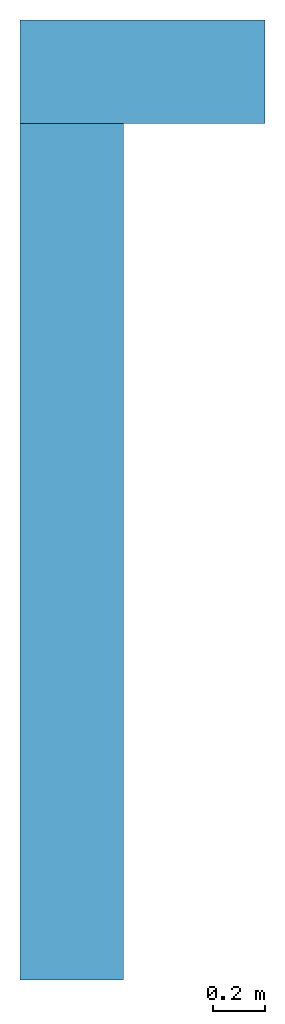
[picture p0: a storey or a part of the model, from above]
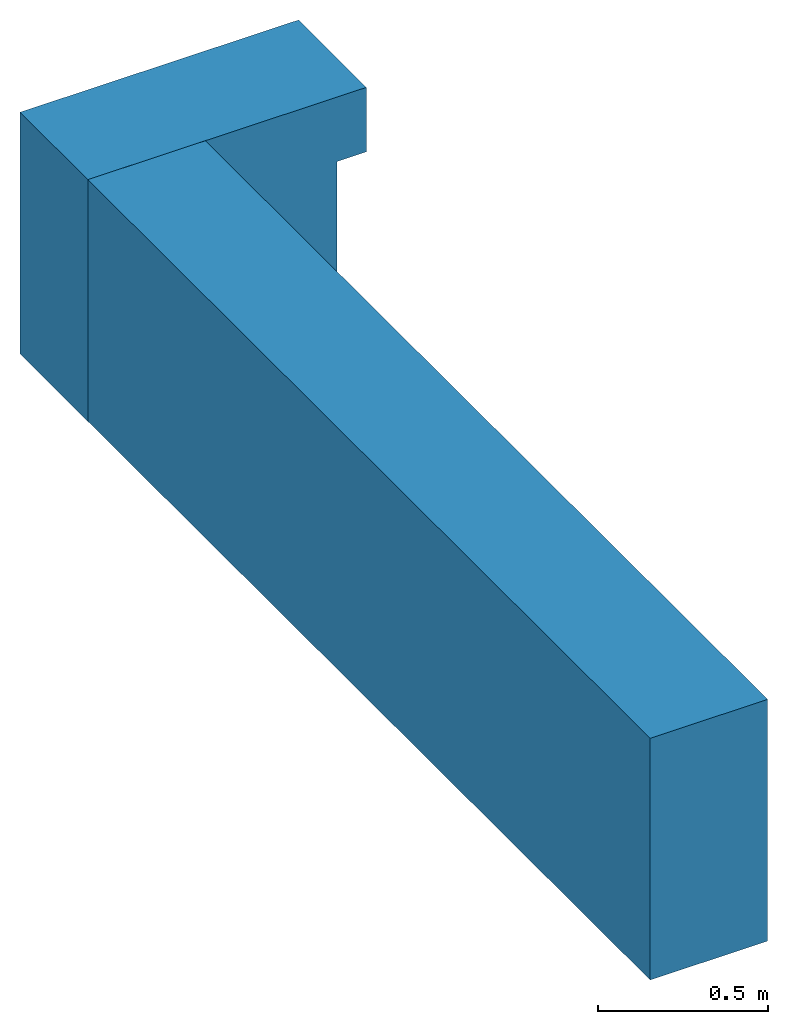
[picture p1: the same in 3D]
Properties of the parts of a building model (IFC2X3), part 1 of 3

# File
Description: ViewDefinition [CoordinationView]
File name: VA006-350-101.1 (EDITED).ifc (Edited by Naviate Simple BIM 2022 version 6)
Time: 2026-03-20T14:23:12+01:00
Written by: ODA SDAI 22.12
Made in: Autodesk Revit 23.1.90.15 (ENU) - IFC 23.3.1.0

# IfcProject
LongName: Trondheim Lufthavn Værnes; Phase: TU 2013

# IfcSite, Default
RefLatitude: 59, 54, 57, 601318; RefLongitude: 10, 44, 59, 999999; RefElevation: 0 mm
Data - Ideate BIMLink: <?xml version="1.0" encoding="utf-8"?><application version="3"> <links> <link> <name>Casework Types</name> <description></description> <elements>CaseworkTypes</elements> <phase>Fase 2</phase> <phase_filter>None</phase_filter> <properties> <property> <name>Id</name> <lookup_1_type></lookup_1_type> <lookup_1_id></lookup_1_id> <type>BUILT_IN_PARAMETER</type> <id>ID_PARAM</id> </property> <property> <name>Family Name</name> <lookup_1_type></lookup_1_type> <lookup_1_id></lookup_1_id> <type>CALCULATED_PROPERTY</type> <id>FamilyName</id> </property> <property> <name>Type Name</name> <lookup_1_type></lookup_1_type> <lookup_1_id></lookup_1_id> <type>CALCULATED_PROPERTY</type> <id>TypeName</id> </property> </properties> </link> <link> <name>Window Types</name> <description></description> <elements>WindowTypes</elements> <phase>Fase 2</phase> <phase_filter>None</phase_filter> <properties> <property> <name>Id</name> <lookup_1_type></lookup_1_type> <lookup_1_id></lookup_1_id> <type>BUILT_IN_PARAMETER</type> <id>ID_PARAM</id> </property> <property> <name>Family Name</name> <lookup_1_type></lookup_1_type> <lookup_1_id></lookup_1_id> <type>CALCULATED_PROPERTY</type> <id>FamilyName</id> </property> <property> <name>Type Name</name> <lookup_1_type></lookup_1_type> <lookup_1_id></lookup_1_id> <type>CALCULATED_PROPERTY</type> <id>TypeName</id> </property> </properties> </link> <link> <name>Wall Types</name> <description></description> <elements>WallTypes</elements> <phase>Fase 1</phase> <phase_filter>Show Complete</phase_filter> <properties> <property> <name>Id</name> <lookup_1_type></lookup_1_type> <lookup_1_id></lookup_1_id> <type>BUILT_IN_PARAMETER</type> <id>ID_PARAM</id> </property> <property> <name>Family Name</name> <lookup_1_type></lookup_1_type> <lookup_1_id></lookup_1_id> <type>BUILT_IN_PARAMETER</type> <id>SYMBOL_FAMILY_NAME_PARAM</id> </property> <property> <name>Type Name</name> <lookup_1_type></lookup_1_type> <lookup_1_id></lookup_1_id> <type>CALCULATED_PROPERTY</type> <id>TypeName</id> </property> </properties> </link> <link> <name>Structural Framing Types</name> <description></description> <elements>StructuralFramingTypes</elements> <phase>Fase 2</phase> <phase_filter>None</phase_filter> <properties> <property> <name>Id</name> <lookup_1_type></lookup_1_type> <lookup_1_id></lookup_1_id> <type>BUILT_IN_PARAMETER</type> <id>ID_PARAM</id> </property> <property> <name>Family Name</name> <lookup_1_type></lookup_1_type> <lookup_1_id></lookup_1_id> <type>CALCULATED_PROPERTY</type> <id>FamilyName</id> </property> <property> <name>Type Name</name> <lookup_1_type></lookup_1_type> <lookup_1_id></lookup_1_id> <type>CALCULATED_PROPERTY</type> <id>TypeName</id> </property> </properties> </link> <link> <name>Structural Foundation Types</name> <description></description> <elements>StructuralFoundationTypes</elements> <phase>Fase 2</phase> <phase_filter>None</phase_filter> <properties> <property> <name>Id</name> <lookup_1_type></lookup_1_type> <lookup_1_id></lookup_1_id> <type>BUILT_IN_PARAMETER</type> <id>ID_PARAM</id> </property> <property> <name>Family Name</name> <lookup_1_type></lookup_1_type> <lookup_1_id></lookup_1_id> <type>CALCULATED_PROPERTY</type> <id>FamilyName</id> </property> <property> <name>Type Name</name> <lookup_1_type></lookup_1_type> <lookup_1_id></lookup_1_id> <type>CALCULATED_PROPERTY</type> <id>TypeName</id> </property> </properties> </link> <link> <name>Structural Column Types</name> <description></description> <elements>StructuralColumnTypes</elements> <phase>Fase 2</phase> <phase_filter>None</phase_filter> <properties> <property> <name>Id</name> <lookup_1_type></lookup_1_type> <lookup_1_id></lookup_1_id> <type>BUILT_IN_PARAMETER</type> <id>ID_PARAM</id> </property> <property> <name>Family Name</name> <lookup_1_type></lookup_1_type> <lookup_1_id></lookup_1_id> <type>CALCULATED_PROPERTY</type> <id>FamilyName</id> </property> <property> <name>Type Name</name> <lookup_1_type></lookup_1_type> <lookup_1_id></lookup_1_id> <type>CALCULATED_PROPERTY</type> <id>TypeName</id> </property> </properties> </link> <link> <name>Stair Types</name> <description></description> <elements>StairTypes</elements> <phase>Fase 2</phase> <phase_filter>None</phase_filter> <properties> <property> <name>Id</name> <lookup_1_type></lookup_1_type> <lookup_1_id></lookup_1_id> <type>BUILT_IN_PARAMETER</type> <id>ID_PARAM</id> </property> <property> <name>Family Name</name> <lookup_1_type></lookup_1_type> <lookup_1_id></lookup_1_id> <type>BUILT_IN_PARAMETER</type> <id>ALL_MODEL_FAMILY_NAME</id> </property> <property> <name>Type Name</name> <lookup_1_type></lookup_1_type> <lookup_1_id></lookup_1_id> <type>CALCULATED_PROPERTY</type> <id>TypeName</id> </property> </properties> </link> <link> <name>Specialty Equipment Types</name> <description></description> <elements>SpecialtyEquipmentTypes</elements> <phase>Fase 2</phase> <phase_filter>None</phase_filter> <properties> <property> <name>Id</name> <lookup_1_type></lookup_1_type> <lookup_1_id></lookup_1_id> <type>BUILT_IN_PARAMETER</type> <id>ID_PARAM</id> </property> <property> <name>Family Name</name> <lookup_1_type></lookup_1_type> <lookup_1_id></lookup_1_id> <type>CALCULATED_PROPERTY</type> <id>FamilyName</id> </property> <property> <name>Type Name</name> <lookup_1_type></lookup_1_type> <lookup_1_id></lookup_1_id> <type>CALCULATED_PROPERTY</type> <id>TypeName</id> </property> </properties> </link> <link> <name>Roof Types</name> <description></description> <elements>RoofTypes</elements> <phase>Fase 2</phase> <phase_filter>None</phase_filter> <properties> <property> <name>Id</name> <lookup_1_type></lookup_1_type> <lookup_1_id></lookup_1_id> <type>BUILT_IN_PARAMETER</type> <id>ID_PARAM</id> </property> <property> <name>Family Name</name> <lookup_1_type></lookup_1_type> <lookup_1_id></lookup_1_id> <type>BUILT_IN_PARAMETER</type> <id>ALL_MODEL_FAMILY_NAME</id> </property> <property> <name>Type Name</name> <lookup_1_type></lookup_1_type> <lookup_1_id></lookup_1_id> <type>CALCULATED_PROPERTY</type> <id>TypeName</id> </property> </properties> </link> <link> <name>Ramp Types</name> <description></description> <elements>RampTypes</elements> <phase>Fase 2</phase> <phase_filter>None</phase_filter> <properties> <property> <name>Id</name> <lookup_1_type></lookup_1_type> <lookup_1_id></lookup_1_id> <type>BUILT_IN_PARAMETER</type> <id>ID_PARAM</id> </property> <property> <name>Family Name</name> <lookup_1_type></lookup_1_type> <lookup_1_id></lookup_1_id> <type>BUILT_IN_PARAMETER</type> <id>ALL_MODEL_FAMILY_NAME</id> </property> <property> <name>Type Name</name> <lookup_1_type></lookup_1_type> <lookup_1_id></lookup_1_id> <type>CALCULATED_PROPERTY</type> <id>TypeName</id> </property> </properties> </link> <link> <name>Railing Types</name> <description></description> <elements>RailingTypes</elements> <phase>Fase 2</phase> <phase_filter>None</phase_filter> <properties> <property> <name>Id</name> <lookup_1_type></lookup_1_type> <lookup_1_id></lookup_1_id> <type>BUILT_IN_PARAMETER</type> <id>ID_PARAM</id> </property> <property> <name>Family Name</name> <lookup_1_type></lookup_1_type> <lookup_1_id></lookup_1_id> <type>BUILT_IN_PARAMETER</type> <id>ALL_MODEL_FAMILY_NAME</id> </property> <property> <name>Type Name</name> <lookup_1_type></lookup_1_type> <lookup_1_id></lookup_1_id> <type>CALCULATED_PROPERTY</type> <id>TypeName</id> </property> </properties> </link> <link> <name>Profile Types</name> <description></description> <elements>ProfileTypes</elements> <phase>Fase 2</phase> <phase_filter>None</phase_filter> <properties> <property> <name>Id</name> <lookup_1_type></lookup_1_type> <lookup_1_id></lookup_1_id> <type>BUILT_IN_PARAMETER</type> <id>ID_PARAM</id> </property> <property> <name>Family Name</name> <lookup_1_type></lookup_1_type> <lookup_1_id></lookup_1_id> <type>BUILT_IN_PARAMETER</type> <id>ALL_MODEL_FAMILY_NAME</id> </property> <property> <name>Type Name</name> <lookup_1_type></lookup_1_type> <lookup_1_id></lookup_1_id> <type>CALCULATED_PROPERTY</type> <id>TypeName</id> </property> </properties> </link> <link> <name>Plumbing Fixture Types</name> <description></description> <elements>PlumbingFixtureTypes</elements> <phase>Fase 2</phase> <phase_filter>None</phase_filter> <properties> <property> <name>Id</name> <lookup_1_type></lookup_1_type> <lookup_1_id></lookup_1_id> <type>BUILT_IN_PARAMETER</type> <id>ID_PARAM</id> </property> <property> <name>Family Name</name> <lookup_1_type></lookup_1_type> <lookup_1_id></lookup_1_id> <type>CALCULATED_PROPERTY</type> <id>FamilyName</id> </property> <property> <name>Type Name</name> <lookup_1_type></lookup_1_type> <lookup_1_id></lookup_1_id> <type>CALCULATED_PROPERTY</type> <id>TypeName</id> </property> </properties> </link> <link> <name>Mechanical Equipment Types</name> <description></description> <elements>MechanicalEquipmentTypes</elements> <phase>Fase 2</phase> <phase_filter>None</phase_filter> <properties> <property> <name>Id</name> <lookup_1_type></lookup_1_type> <lookup_1_id></lookup_1_id> <type>BUILT_IN_PARAMETER</type> <id>ID_PARAM</id> </property> <property> <name>Family Name</name> <lookup_1_type></lookup_1_type> <lookup_1_id></lookup_1_id> <type>CALCULATED_PROPERTY</type> <id>FamilyName</id> </property> <property> <name>Type Name</name> <lookup_1_type></lookup_1_type> <lookup_1_id></lookup_1_id> <type>CALCULATED_PROPERTY</type> <id>TypeName</id> </property> </properties> </link> <link> <name>Mass Types</name> <description></description> <elements>MassTypes</elements> <phase>Fase 2</phase> <phase_filter>None</phase_filter> <properties> <property> <name>Id</name> <lookup_1_type></lookup_1_type> <lookup_1_id></lookup_1_id> <type>BUILT_IN_PARAMETER</type> <id>ID_PARAM</id> </property> <property> <name>Family Name</name> <lookup_1_type></lookup_1_type> <lookup_1_id></lookup_1_id> <type>CALCULATED_PROPERTY</type> <id>FamilyName</id> </property> <property> <name>Type Name</name> <lookup_1_type></lookup_1_type> <lookup_1_id></lookup_1_id> <type>CALCULATED_PROPERTY</type> <id>TypeName</id> </property> </properties> </link> <link> <name>Generic Model Types</name> <description></description> <elements>GenericModelTypes</elements> <phase>Fase 2</phase> <phase_filter>None</phase_filter> <properties> <property> <name>Id</name> <lookup_1_type></lookup_1_type> <lookup_1_id></lookup_1_id> <type>BUILT_IN_PARAMETER</type> <id>ID_PARAM</id> </property> <property> <name>Family Name</name> <lookup_1_type></lookup_1_type> <lookup_1_id></lookup_1_id> <type>CALCULATED_PROPERTY</type> <id>FamilyName</id> </property> <property> <name>Type Name</name> <lookup_1_type></lookup_1_type> <lookup_1_id></lookup_1_id> <type>CALCULATED_PROPERTY</type> <id>TypeName</id> </property> </properties> </link> <link> <name>Column Types</name> <description></description> <elements>ColumnTypes</elements> <phase>Fase 2</phase> <phase_filter>None</phase_filter> <properties> <property> <name>Id</name> <lookup_1_type></lookup_1_type> <lookup_1_id></lookup_1_id> <type>BUILT_IN_PARAMETER</type> <id>ID_PARAM</id> </property> <property> <name>Family Name</name> <lookup_1_type></lookup_1_type> <lookup_1_id></lookup_1_id> <type>CALCULATED_PROPERTY</type> <id>FamilyName</id> </property> <property> <name>Type Name</name> <lookup_1_type></lookup_1_type> <lookup_1_id></lookup_1_id> <type>CALCULATED_PROPERTY</type> <id>TypeName</id> </property> </properties> </link> <link> <name>Columns</name> <description></description> <elements>ColumnInstances</elements> <phase>Fase 2</phase> <phase_filter>None</phase_filter> <properties> <property> <name>Id</name> <lookup_1_type></lookup_1_type> <lookup_1_id></lookup_1_id> <type>BUILT_IN_PARAMETER</type> <id>ID_PARAM</id> </property> </properties> </link> <link> <name>Door Types</name> <description></description> <elements>DoorTypes</elements> <phase>Fase 2</phase> <phase_filter>None</phase_filter> <properties> <property> <name>Id</name> <lookup_1_type></lookup_1_type> <lookup_1_id></lookup_1_id> <type>BUILT_IN_PARAMETER</type> <id>ID_PARAM</id> </property> <property> <name>Family Name</name> <lookup_1_type></lookup_1_type> <lookup_1_id></lookup_1_id> <type>CALCULATED_PROPERTY</type> <id>FamilyName</id> </property> <property> <name>Type Name</name> <lookup_1_type></lookup_1_type> <lookup_1_id></lookup_1_id> <type>CALCULATED_PROPERTY</type> <id>TypeName</id> </property> </properties> </link> <link> <name>Door Types 2</name> <description></description> <elements>DoorTypes</elements> <phase>Fase 1</phase> <phase_filter>Show Complete</phase_filter> <properties> <property> <name>Id</name> <lookup_1_type></lookup_1_type> <lookup_1_id></lookup_1_id> <type>BUILT_IN_PARAMETER</type> <id>ID_PARAM</id> </property> <property> <name>Family Name</name> <lookup_1_type></lookup_1_type> <lookup_1_id></lookup_1_id> <type>CALCULATED_PROPERTY</type> <id>FamilyName</id> </property> <property> <name>Type Name</name> <lookup_1_type></lookup_1_type> <lookup_1_id></lookup_1_id> <type>CALCULATED_PROPERTY</type> <id>TypeName</id> </property> </properties> </link> <link> <name>Ceiling Types</name> <description></description> <elements>CeilingTypes</elements> <phase>Fase 2</phase> <phase_filter>None</phase_filter> <properties> <property> <name>Id</name> <lookup_1_type></lookup_1_type> <lookup_1_id></lookup_1_id> <type>BUILT_IN_PARAMETER</type> <id>ID_PARAM</id> </property> <property> <name>Family Name</name> <lookup_1_type></lookup_1_type> <lookup_1_id></lookup_1_id> <type>BUILT_IN_PARAMETER</type> <id>ALL_MODEL_FAMILY_NAME</id> </property> <property> <name>Type Name</name> <lookup_1_type></lookup_1_type> <lookup_1_id></lookup_1_id> <type>CALCULATED_PROPERTY</type> <id>TypeName</id> </property> </properties> </link> <link> <name>Ceilings</name> <description></description> <elements>CeilingInstances</elements> <phase>Fase 2</phase> <phase_filter>None</phase_filter> <properties> <property> <name>Id</name> <lookup_1_type></lookup_1_type> <lookup_1_id></lookup_1_id> <type>BUILT_IN_PARAMETER</type> <id>ID_PARAM</id> </property> <property> <name>Family Name</name> <lookup_1_type>BUILT_IN_PARAMETER</lookup_1_type> <lookup_1_id>SYMBOL_ID_PARAM</lookup_1_id> <type>BUILT_IN_PARAMETER</type> <id>ALL_MODEL_FAMILY_NAME</id> </property> <property> <name>Type Name</name> <lookup_1_type>BUILT_IN_PARAMETER</lookup_1_type> <lookup_1_id>SYMBOL_ID_PARAM</lookup_1_id> <type>CALCULATED_PROPERTY</type> <id>TypeName</id> </property> </properties> </link> <link> <name>Furniture Types</name> <description></description> <elements>FurnitureTypes</elements> <phase>Fase 2</phase> <phase_filter>None</phase_filter> <properties> <property> <name>Id</name> <lookup_1_type></lookup_1_type> <lookup_1_id></lookup_1_id> <type>BUILT_IN_PARAMETER</type> <id>ID_PARAM</id> </property> <property> <name>Family Name</name> <lookup_1_type></lookup_1_type> <lookup_1_id></lookup_1_id> <type>CALCULATED_PROPERTY</type> <id>FamilyName</id> </property> <property> <name>Type Name</name> <lookup_1_type></lookup_1_type> <lookup_1_id></lookup_1_id> <type>CALCULATED_PROPERTY</type> <id>TypeName</id> </property> </properties> </link> <link> <name>Furniture System Types</name> <description></description> <elements>FurnitureSystemTypes</elements> <phase>Fase 2</phase> <phase_filter>None</phase_filter> <properties> <property> <name>Id</name> <lookup_1_type></lookup_1_type> <lookup_1_id></lookup_1_id> <type>BUILT_IN_PARAMETER</type> <id>ID_PARAM</id> </property> <property> <name>Family Name</name> <lookup_1_type></lookup_1_type> <lookup_1_id></lookup_1_id> <type>CALCULATED_PROPERTY</type> <id>FamilyName</id> </property> <property> <name>Type Name</name> <lookup_1_type></lookup_1_type> <lookup_1_id></lookup_1_id> <type>CALCULATED_PROPERTY</type> <id>TypeName</id> </property> </properties> </link> <link> <name>Sheets</name> <description></description> <elements>Sheets</elements> <phase>Fase 1</phase> <phase_filter>None</phase_filter> <properties> <property> <name>Id</name> <lookup_1_type></lookup_1_type> <lookup_1_id></lookup_1_id> <type>BUILT_IN_PARAMETER</type> <id>ID_PARAM</id> </property> </properties> </link> <link> <name>Walls</name> <description></description> <elements>WallInstances</elements> <phase>Fase 2</phase> <phase_filter>None</phase_filter> <properties> <property> <name>Id</name> <lookup_1_type></lookup_1_type> <lookup_1_id></lookup_1_id> <type>BUILT_IN_PARAMETER</type> <id>ID_PARAM</id> </property> </properties> </link> <link> <name>Wall types all official names</name> <description></description> <elements>WallTypes</elements> <phase>Fase 1</phase> <phase_filter>None</phase_filter> <properties> <property> <name>Id</name> <lookup_1_type></lookup_1_type> <lookup_1_id></lookup_1_id> <type>BUILT_IN_PARAMETER</type> <id>ID_PARAM</id> </property> <property> <name>Family Name</name> <lookup_1_type></lookup_1_type> <lookup_1_id></lookup_1_id> <type>BUILT_IN_PARAMETER</type> <id>ALL_MODEL_FAMILY_NAME</id> </property> <property> <name>Type Name</name> <lookup_1_type></lookup_1_type> <lookup_1_id></lookup_1_id> <type>CALCULATED_PROPERTY</type> <id>TypeName</id> </property> </properties> </link> <link> <name>test</name> <description></description> <elements>WallTypes</elements> <phase>Fase 1</phase> <phase_filter>None</phase_filter> <properties> <property> <name>Id</name> <lookup_1_type></lookup_1_type> <lookup_1_id></lookup_1_id> <type>BUILT_IN_PARAMETER</type> <id>ID_PARAM</id> </property> <property> <name>Family Name</name> <lookup_1_type></lookup_1_type> <lookup_1_id></lookup_1_id> <type>BUILT_IN_PARAMETER</type> <id>ALL_MODEL_FAMILY_NAME</id> </property> <property> <name>Type Name</name> <lookup_1_type></lookup_1_type> <lookup_1_id></lookup_1_id> <type>CALCULATED_PROPERTY</type> <id>TypeName</id> </property> </properties> </link> </links></application>
Text - 01_Modellfil: va006-a-220-1-0001.rvt
Identity Data - Workset: Project Info
Other - RIE, firma: RAMBØLL AS; Project Status: TU 2013; Saksbehandler: MR; Project Address: Skriv adresse her; Category: Project Information; Prosjektansvarlig: TILBUD E203 TETT BYGG; RIV, telefon: +47 7310 6200; RIB, telefon: +47 7289 3750; Project Name: Trondheim Lufthavn Værnes; RIV, firma: MULTICONSULT AS; RIB, firma: NORCONSULT; RIE, telefon: +47 7389 1000

# IfcBuilding
Pset_BuildingCommon - NumberOfStoreys: 9
Text - 01_Modellfil: va006-a-220-1-0001.rvt
Identity Data - Workset: Project Info
Data - Ideate BIMLink: <?xml version="1.0" encoding="utf-8"?><application version="3"> <links> <link> <name>Casework Types</name> <description></description> <elements>CaseworkTypes</elements> <phase>Fase 2</phase> <phase_filter>None</phase_filter> <properties> <property> <name>Id</name> <lookup_1_type></lookup_1_type> <lookup_1_id></lookup_1_id> <type>BUILT_IN_PARAMETER</type> <id>ID_PARAM</id> </property> <property> <name>Family Name</name> <lookup_1_type></lookup_1_type> <lookup_1_id></lookup_1_id> <type>CALCULATED_PROPERTY</type> <id>FamilyName</id> </property> <property> <name>Type Name</name> <lookup_1_type></lookup_1_type> <lookup_1_id></lookup_1_id> <type>CALCULATED_PROPERTY</type> <id>TypeName</id> </property> </properties> </link> <link> <name>Window Types</name> <description></description> <elements>WindowTypes</elements> <phase>Fase 2</phase> <phase_filter>None</phase_filter> <properties> <property> <name>Id</name> <lookup_1_type></lookup_1_type> <lookup_1_id></lookup_1_id> <type>BUILT_IN_PARAMETER</type> <id>ID_PARAM</id> </property> <property> <name>Family Name</name> <lookup_1_type></lookup_1_type> <lookup_1_id></lookup_1_id> <type>CALCULATED_PROPERTY</type> <id>FamilyName</id> </property> <property> <name>Type Name</name> <lookup_1_type></lookup_1_type> <lookup_1_id></lookup_1_id> <type>CALCULATED_PROPERTY</type> <id>TypeName</id> </property> </properties> </link> <link> <name>Wall Types</name> <description></description> <elements>WallTypes</elements> <phase>Fase 1</phase> <phase_filter>Show Complete</phase_filter> <properties> <property> <name>Id</name> <lookup_1_type></lookup_1_type> <lookup_1_id></lookup_1_id> <type>BUILT_IN_PARAMETER</type> <id>ID_PARAM</id> </property> <property> <name>Family Name</name> <lookup_1_type></lookup_1_type> <lookup_1_id></lookup_1_id> <type>BUILT_IN_PARAMETER</type> <id>SYMBOL_FAMILY_NAME_PARAM</id> </property> <property> <name>Type Name</name> <lookup_1_type></lookup_1_type> <lookup_1_id></lookup_1_id> <type>CALCULATED_PROPERTY</type> <id>TypeName</id> </property> </properties> </link> <link> <name>Structural Framing Types</name> <description></description> <elements>StructuralFramingTypes</elements> <phase>Fase 2</phase> <phase_filter>None</phase_filter> <properties> <property> <name>Id</name> <lookup_1_type></lookup_1_type> <lookup_1_id></lookup_1_id> <type>BUILT_IN_PARAMETER</type> <id>ID_PARAM</id> </property> <property> <name>Family Name</name> <lookup_1_type></lookup_1_type> <lookup_1_id></lookup_1_id> <type>CALCULATED_PROPERTY</type> <id>FamilyName</id> </property> <property> <name>Type Name</name> <lookup_1_type></lookup_1_type> <lookup_1_id></lookup_1_id> <type>CALCULATED_PROPERTY</type> <id>TypeName</id> </property> </properties> </link> <link> <name>Structural Foundation Types</name> <description></description> <elements>StructuralFoundationTypes</elements> <phase>Fase 2</phase> <phase_filter>None</phase_filter> <properties> <property> <name>Id</name> <lookup_1_type></lookup_1_type> <lookup_1_id></lookup_1_id> <type>BUILT_IN_PARAMETER</type> <id>ID_PARAM</id> </property> <property> <name>Family Name</name> <lookup_1_type></lookup_1_type> <lookup_1_id></lookup_1_id> <type>CALCULATED_PROPERTY</type> <id>FamilyName</id> </property> <property> <name>Type Name</name> <lookup_1_type></lookup_1_type> <lookup_1_id></lookup_1_id> <type>CALCULATED_PROPERTY</type> <id>TypeName</id> </property> </properties> </link> <link> <name>Structural Column Types</name> <description></description> <elements>StructuralColumnTypes</elements> <phase>Fase 2</phase> <phase_filter>None</phase_filter> <properties> <property> <name>Id</name> <lookup_1_type></lookup_1_type> <lookup_1_id></lookup_1_id> <type>BUILT_IN_PARAMETER</type> <id>ID_PARAM</id> </property> <property> <name>Family Name</name> <lookup_1_type></lookup_1_type> <lookup_1_id></lookup_1_id> <type>CALCULATED_PROPERTY</type> <id>FamilyName</id> </property> <property> <name>Type Name</name> <lookup_1_type></lookup_1_type> <lookup_1_id></lookup_1_id> <type>CALCULATED_PROPERTY</type> <id>TypeName</id> </property> </properties> </link> <link> <name>Stair Types</name> <description></description> <elements>StairTypes</elements> <phase>Fase 2</phase> <phase_filter>None</phase_filter> <properties> <property> <name>Id</name> <lookup_1_type></lookup_1_type> <lookup_1_id></lookup_1_id> <type>BUILT_IN_PARAMETER</type> <id>ID_PARAM</id> </property> <property> <name>Family Name</name> <lookup_1_type></lookup_1_type> <lookup_1_id></lookup_1_id> <type>BUILT_IN_PARAMETER</type> <id>ALL_MODEL_FAMILY_NAME</id> </property> <property> <name>Type Name</name> <lookup_1_type></lookup_1_type> <lookup_1_id></lookup_1_id> <type>CALCULATED_PROPERTY</type> <id>TypeName</id> </property> </properties> </link> <link> <name>Specialty Equipment Types</name> <description></description> <elements>SpecialtyEquipmentTypes</elements> <phase>Fase 2</phase> <phase_filter>None</phase_filter> <properties> <property> <name>Id</name> <lookup_1_type></lookup_1_type> <lookup_1_id></lookup_1_id> <type>BUILT_IN_PARAMETER</type> <id>ID_PARAM</id> </property> <property> <name>Family Name</name> <lookup_1_type></lookup_1_type> <lookup_1_id></lookup_1_id> <type>CALCULATED_PROPERTY</type> <id>FamilyName</id> </property> <property> <name>Type Name</name> <lookup_1_type></lookup_1_type> <lookup_1_id></lookup_1_id> <type>CALCULATED_PROPERTY</type> <id>TypeName</id> </property> </properties> </link> <link> <name>Roof Types</name> <description></description> <elements>RoofTypes</elements> <phase>Fase 2</phase> <phase_filter>None</phase_filter> <properties> <property> <name>Id</name> <lookup_1_type></lookup_1_type> <lookup_1_id></lookup_1_id> <type>BUILT_IN_PARAMETER</type> <id>ID_PARAM</id> </property> <property> <name>Family Name</name> <lookup_1_type></lookup_1_type> <lookup_1_id></lookup_1_id> <type>BUILT_IN_PARAMETER</type> <id>ALL_MODEL_FAMILY_NAME</id> </property> <property> <name>Type Name</name> <lookup_1_type></lookup_1_type> <lookup_1_id></lookup_1_id> <type>CALCULATED_PROPERTY</type> <id>TypeName</id> </property> </properties> </link> <link> <name>Ramp Types</name> <description></description> <elements>RampTypes</elements> <phase>Fase 2</phase> <phase_filter>None</phase_filter> <properties> <property> <name>Id</name> <lookup_1_type></lookup_1_type> <lookup_1_id></lookup_1_id> <type>BUILT_IN_PARAMETER</type> <id>ID_PARAM</id> </property> <property> <name>Family Name</name> <lookup_1_type></lookup_1_type> <lookup_1_id></lookup_1_id> <type>BUILT_IN_PARAMETER</type> <id>ALL_MODEL_FAMILY_NAME</id> </property> <property> <name>Type Name</name> <lookup_1_type></lookup_1_type> <lookup_1_id></lookup_1_id> <type>CALCULATED_PROPERTY</type> <id>TypeName</id> </property> </properties> </link> <link> <name>Railing Types</name> <description></description> <elements>RailingTypes</elements> <phase>Fase 2</phase> <phase_filter>None</phase_filter> <properties> <property> <name>Id</name> <lookup_1_type></lookup_1_type> <lookup_1_id></lookup_1_id> <type>BUILT_IN_PARAMETER</type> <id>ID_PARAM</id> </property> <property> <name>Family Name</name> <lookup_1_type></lookup_1_type> <lookup_1_id></lookup_1_id> <type>BUILT_IN_PARAMETER</type> <id>ALL_MODEL_FAMILY_NAME</id> </property> <property> <name>Type Name</name> <lookup_1_type></lookup_1_type> <lookup_1_id></lookup_1_id> <type>CALCULATED_PROPERTY</type> <id>TypeName</id> </property> </properties> </link> <link> <name>Profile Types</name> <description></description> <elements>ProfileTypes</elements> <phase>Fase 2</phase> <phase_filter>None</phase_filter> <properties> <property> <name>Id</name> <lookup_1_type></lookup_1_type> <lookup_1_id></lookup_1_id> <type>BUILT_IN_PARAMETER</type> <id>ID_PARAM</id> </property> <property> <name>Family Name</name> <lookup_1_type></lookup_1_type> <lookup_1_id></lookup_1_id> <type>BUILT_IN_PARAMETER</type> <id>ALL_MODEL_FAMILY_NAME</id> </property> <property> <name>Type Name</name> <lookup_1_type></lookup_1_type> <lookup_1_id></lookup_1_id> <type>CALCULATED_PROPERTY</type> <id>TypeName</id> </property> </properties> </link> <link> <name>Plumbing Fixture Types</name> <description></description> <elements>PlumbingFixtureTypes</elements> <phase>Fase 2</phase> <phase_filter>None</phase_filter> <properties> <property> <name>Id</name> <lookup_1_type></lookup_1_type> <lookup_1_id></lookup_1_id> <type>BUILT_IN_PARAMETER</type> <id>ID_PARAM</id> </property> <property> <name>Family Name</name> <lookup_1_type></lookup_1_type> <lookup_1_id></lookup_1_id> <type>CALCULATED_PROPERTY</type> <id>FamilyName</id> </property> <property> <name>Type Name</name> <lookup_1_type></lookup_1_type> <lookup_1_id></lookup_1_id> <type>CALCULATED_PROPERTY</type> <id>TypeName</id> </property> </properties> </link> <link> <name>Mechanical Equipment Types</name> <description></description> <elements>MechanicalEquipmentTypes</elements> <phase>Fase 2</phase> <phase_filter>None</phase_filter> <properties> <property> <name>Id</name> <lookup_1_type></lookup_1_type> <lookup_1_id></lookup_1_id> <type>BUILT_IN_PARAMETER</type> <id>ID_PARAM</id> </property> <property> <name>Family Name</name> <lookup_1_type></lookup_1_type> <lookup_1_id></lookup_1_id> <type>CALCULATED_PROPERTY</type> <id>FamilyName</id> </property> <property> <name>Type Name</name> <lookup_1_type></lookup_1_type> <lookup_1_id></lookup_1_id> <type>CALCULATED_PROPERTY</type> <id>TypeName</id> </property> </properties> </link> <link> <name>Mass Types</name> <description></description> <elements>MassTypes</elements> <phase>Fase 2</phase> <phase_filter>None</phase_filter> <properties> <property> <name>Id</name> <lookup_1_type></lookup_1_type> <lookup_1_id></lookup_1_id> <type>BUILT_IN_PARAMETER</type> <id>ID_PARAM</id> </property> <property> <name>Family Name</name> <lookup_1_type></lookup_1_type> <lookup_1_id></lookup_1_id> <type>CALCULATED_PROPERTY</type> <id>FamilyName</id> </property> <property> <name>Type Name</name> <lookup_1_type></lookup_1_type> <lookup_1_id></lookup_1_id> <type>CALCULATED_PROPERTY</type> <id>TypeName</id> </property> </properties> </link> <link> <name>Generic Model Types</name> <description></description> <elements>GenericModelTypes</elements> <phase>Fase 2</phase> <phase_filter>None</phase_filter> <properties> <property> <name>Id</name> <lookup_1_type></lookup_1_type> <lookup_1_id></lookup_1_id> <type>BUILT_IN_PARAMETER</type> <id>ID_PARAM</id> </property> <property> <name>Family Name</name> <lookup_1_type></lookup_1_type> <lookup_1_id></lookup_1_id> <type>CALCULATED_PROPERTY</type> <id>FamilyName</id> </property> <property> <name>Type Name</name> <lookup_1_type></lookup_1_type> <lookup_1_id></lookup_1_id> <type>CALCULATED_PROPERTY</type> <id>TypeName</id> </property> </properties> </link> <link> <name>Column Types</name> <description></description> <elements>ColumnTypes</elements> <phase>Fase 2</phase> <phase_filter>None</phase_filter> <properties> <property> <name>Id</name> <lookup_1_type></lookup_1_type> <lookup_1_id></lookup_1_id> <type>BUILT_IN_PARAMETER</type> <id>ID_PARAM</id> </property> <property> <name>Family Name</name> <lookup_1_type></lookup_1_type> <lookup_1_id></lookup_1_id> <type>CALCULATED_PROPERTY</type> <id>FamilyName</id> </property> <property> <name>Type Name</name> <lookup_1_type></lookup_1_type> <lookup_1_id></lookup_1_id> <type>CALCULATED_PROPERTY</type> <id>TypeName</id> </property> </properties> </link> <link> <name>Columns</name> <description></description> <elements>ColumnInstances</elements> <phase>Fase 2</phase> <phase_filter>None</phase_filter> <properties> <property> <name>Id</name> <lookup_1_type></lookup_1_type> <lookup_1_id></lookup_1_id> <type>BUILT_IN_PARAMETER</type> <id>ID_PARAM</id> </property> </properties> </link> <link> <name>Door Types</name> <description></description> <elements>DoorTypes</elements> <phase>Fase 2</phase> <phase_filter>None</phase_filter> <properties> <property> <name>Id</name> <lookup_1_type></lookup_1_type> <lookup_1_id></lookup_1_id> <type>BUILT_IN_PARAMETER</type> <id>ID_PARAM</id> </property> <property> <name>Family Name</name> <lookup_1_type></lookup_1_type> <lookup_1_id></lookup_1_id> <type>CALCULATED_PROPERTY</type> <id>FamilyName</id> </property> <property> <name>Type Name</name> <lookup_1_type></lookup_1_type> <lookup_1_id></lookup_1_id> <type>CALCULATED_PROPERTY</type> <id>TypeName</id> </property> </properties> </link> <link> <name>Door Types 2</name> <description></description> <elements>DoorTypes</elements> <phase>Fase 1</phase> <phase_filter>Show Complete</phase_filter> <properties> <property> <name>Id</name> <lookup_1_type></lookup_1_type> <lookup_1_id></lookup_1_id> <type>BUILT_IN_PARAMETER</type> <id>ID_PARAM</id> </property> <property> <name>Family Name</name> <lookup_1_type></lookup_1_type> <lookup_1_id></lookup_1_id> <type>CALCULATED_PROPERTY</type> <id>FamilyName</id> </property> <property> <name>Type Name</name> <lookup_1_type></lookup_1_type> <lookup_1_id></lookup_1_id> <type>CALCULATED_PROPERTY</type> <id>TypeName</id> </property> </properties> </link> <link> <name>Ceiling Types</name> <description></description> <elements>CeilingTypes</elements> <phase>Fase 2</phase> <phase_filter>None</phase_filter> <properties> <property> <name>Id</name> <lookup_1_type></lookup_1_type> <lookup_1_id></lookup_1_id> <type>BUILT_IN_PARAMETER</type> <id>ID_PARAM</id> </property> <property> <name>Family Name</name> <lookup_1_type></lookup_1_type> <lookup_1_id></lookup_1_id> <type>BUILT_IN_PARAMETER</type> <id>ALL_MODEL_FAMILY_NAME</id> </property> <property> <name>Type Name</name> <lookup_1_type></lookup_1_type> <lookup_1_id></lookup_1_id> <type>CALCULATED_PROPERTY</type> <id>TypeName</id> </property> </properties> </link> <link> <name>Ceilings</name> <description></description> <elements>CeilingInstances</elements> <phase>Fase 2</phase> <phase_filter>None</phase_filter> <properties> <property> <name>Id</name> <lookup_1_type></lookup_1_type> <lookup_1_id></lookup_1_id> <type>BUILT_IN_PARAMETER</type> <id>ID_PARAM</id> </property> <property> <name>Family Name</name> <lookup_1_type>BUILT_IN_PARAMETER</lookup_1_type> <lookup_1_id>SYMBOL_ID_PARAM</lookup_1_id> <type>BUILT_IN_PARAMETER</type> <id>ALL_MODEL_FAMILY_NAME</id> </property> <property> <name>Type Name</name> <lookup_1_type>BUILT_IN_PARAMETER</lookup_1_type> <lookup_1_id>SYMBOL_ID_PARAM</lookup_1_id> <type>CALCULATED_PROPERTY</type> <id>TypeName</id> </property> </properties> </link> <link> <name>Furniture Types</name> <description></description> <elements>FurnitureTypes</elements> <phase>Fase 2</phase> <phase_filter>None</phase_filter> <properties> <property> <name>Id</name> <lookup_1_type></lookup_1_type> <lookup_1_id></lookup_1_id> <type>BUILT_IN_PARAMETER</type> <id>ID_PARAM</id> </property> <property> <name>Family Name</name> <lookup_1_type></lookup_1_type> <lookup_1_id></lookup_1_id> <type>CALCULATED_PROPERTY</type> <id>FamilyName</id> </property> <property> <name>Type Name</name> <lookup_1_type></lookup_1_type> <lookup_1_id></lookup_1_id> <type>CALCULATED_PROPERTY</type> <id>TypeName</id> </property> </properties> </link> <link> <name>Furniture System Types</name> <description></description> <elements>FurnitureSystemTypes</elements> <phase>Fase 2</phase> <phase_filter>None</phase_filter> <properties> <property> <name>Id</name> <lookup_1_type></lookup_1_type> <lookup_1_id></lookup_1_id> <type>BUILT_IN_PARAMETER</type> <id>ID_PARAM</id> </property> <property> <name>Family Name</name> <lookup_1_type></lookup_1_type> <lookup_1_id></lookup_1_id> <type>CALCULATED_PROPERTY</type> <id>FamilyName</id> </property> <property> <name>Type Name</name> <lookup_1_type></lookup_1_type> <lookup_1_id></lookup_1_id> <type>CALCULATED_PROPERTY</type> <id>TypeName</id> </property> </properties> </link> <link> <name>Sheets</name> <description></description> <elements>Sheets</elements> <phase>Fase 1</phase> <phase_filter>None</phase_filter> <properties> <property> <name>Id</name> <lookup_1_type></lookup_1_type> <lookup_1_id></lookup_1_id> <type>BUILT_IN_PARAMETER</type> <id>ID_PARAM</id> </property> </properties> </link> <link> <name>Walls</name> <description></description> <elements>WallInstances</elements> <phase>Fase 2</phase> <phase_filter>None</phase_filter> <properties> <property> <name>Id</name> <lookup_1_type></lookup_1_type> <lookup_1_id></lookup_1_id> <type>BUILT_IN_PARAMETER</type> <id>ID_PARAM</id> </property> </properties> </link> <link> <name>Wall types all official names</name> <description></description> <elements>WallTypes</elements> <phase>Fase 1</phase> <phase_filter>None</phase_filter> <properties> <property> <name>Id</name> <lookup_1_type></lookup_1_type> <lookup_1_id></lookup_1_id> <type>BUILT_IN_PARAMETER</type> <id>ID_PARAM</id> </property> <property> <name>Family Name</name> <lookup_1_type></lookup_1_type> <lookup_1_id></lookup_1_id> <type>BUILT_IN_PARAMETER</type> <id>ALL_MODEL_FAMILY_NAME</id> </property> <property> <name>Type Name</name> <lookup_1_type></lookup_1_type> <lookup_1_id></lookup_1_id> <type>CALCULATED_PROPERTY</type> <id>TypeName</id> </property> </properties> </link> <link> <name>test</name> <description></description> <elements>WallTypes</elements> <phase>Fase 1</phase> <phase_filter>None</phase_filter> <properties> <property> <name>Id</name> <lookup_1_type></lookup_1_type> <lookup_1_id></lookup_1_id> <type>BUILT_IN_PARAMETER</type> <id>ID_PARAM</id> </property> <property> <name>Family Name</name> <lookup_1_type></lookup_1_type> <lookup_1_id></lookup_1_id> <type>BUILT_IN_PARAMETER</type> <id>ALL_MODEL_FAMILY_NAME</id> </property> <property> <name>Type Name</name> <lookup_1_type></lookup_1_type> <lookup_1_id></lookup_1_id> <type>CALCULATED_PROPERTY</type> <id>TypeName</id> </property> </properties> </link> </links></application>
Other - RIE, firma: RAMBØLL AS; Project Status: TU 2013; Saksbehandler: MR; Project Address: Skriv adresse her; Category: Project Information; Prosjektansvarlig: TILBUD E203 TETT BYGG; RIV, telefon: +47 7310 6200; RIB, telefon: +47 7289 3750; Project Name: Trondheim Lufthavn Værnes; RIV, firma: MULTICONSULT AS; RIB, firma: NORCONSULT; RIE, telefon: +47 7389 1000

# IfcBuildingStorey: Level:SKISSE, XX - C +8,70
LongName: XX - C +8,70; Elevation: 8700 mm
Identity Data - Name: XX - C +8,70; Structural: no; Building Story: yes; Workset: Shared Levels and Grids
Dimensions - Computation Height: 0 mm
Graphics(Type) - Symbol: NSW Kote - Triangel med kote, ISO 2,5 mm (fault, do not use -DC) : NSW Kote - Triangel med kote, ISO 2,5 mm; Line Pattern: Centre; Color: 0; Symbol at End 1 Default: yes; Symbol at End 2 Default: no; Line Weight: 4
Pset_ProductRequirements - Name: XX - C +8,70; sets with these values: 2
Constraints - Elevation: 8700 mm
Identity Data(Type) - Workset: Level Types; Type Name: SKISSE
Other - Type: SKISSE; Type Id: 7725099; Category: Levels; Family and Type: Level: SKISSE; Family: Level
Constraints(Type) - Elevation Base: Project Base Point
Other(Type) - Category: Levels; Family Name: Level

# IfcBuildingStorey: Level:TA (4)
Identity Data(Type) - Workset: Level Types; Type Name: TA
Other - Family and Type: Level: TA; Type Id: 7724934; Type: TA; Category: Levels; Family: Level
Graphics(Type) - Symbol: NSW Kote - Triangel med kote, ISO 2,5 mm (fault, do not use -DC) : NSW Kote - Triangel med kote, ISO 2,5 mm; Line Pattern: Centre; Color: 0; Symbol at End 1 Default: yes; Symbol at End 2 Default: no; Line Weight: 4
Constraints(Type) - Elevation Base: Project Base Point
Identity Data - Structural: no; Building Story: yes; Workset: Shared Levels and Grids
Other(Type) - Category: Levels; Family Name: Level
Name | LongName = Identity Data, Name | Elevation (mm) = Constraints, Elevation (mm) | Computation Height (mm)
U01 Hovedetasje | U01 Hovedetasje | 6250 | 1320 | Pset_AirSideSystemInformation - Name: U01 Hovedetasje; sets with these values: 2; Identity Data - Etasje Klassifisering: Hovedetasje
H01 Hovedetasje | H01 Hovedetasje | 9320 | 1860 | Pset_AirSideSystemInformation - Name: H01 Hovedetasje; sets with these values: 2; Identity Data - Etasje Klassifisering: Hovedetasje
XX - C +10,75 TA E1 | XX - C +10,75 TA E1 | 10750 | 1200 | Pset_ProductRequirements - Name: XX - C +10,75 TA E1; sets with these values: 2
XX - C +15,37 TA E2 | XX - C +15,37 TA E2 | 15370 | 1200 | Pset_ProductRequirements - Name: XX - C +15,37 TA E2; sets with these values: 2

# IfcBuildingStorey: Level:TB (2)
Other - Family and Type: Level: TB; Type: TB; Type Id: 7617874; Category: Levels; Family: Level
Pset_AirSideSystemInformation - sets with these values: 2
Identity Data - Structural: no; Building Story: yes; Workset: Shared Levels and Grids
Graphics(Type) - Symbol: NSW Kote - Triangel med kote, ISO 2,5 mm (fault, do not use -DC) : NSW Kote - Triangel med kote, ISO 2,5 mm; Line Pattern: Centre; Color: 0; Symbol at End 1 Default: yes; Symbol at End 2 Default: no; Line Weight: 4
Identity Data(Type) - Workset: Level Types; Type Name: TB
Constraints(Type) - Elevation Base: Project Base Point
Other(Type) - Category: Levels; Family Name: Level
Name | LongName = Pset_AirSideSystemInformation, Name = Identity Data, Name | Elevation (mm) = Constraints, Elevation (mm) | Computation Height (mm)
XX - C +7,57 TB U1 | XX - C +7,57 TB U1 | 7570 | 1200
XX - C +9,05 | XX - C +9,05 | 9050 | 0

# IfcBuildingElementProxy: Generic Models 5:Generic Models 5, Generic Models 5:Generic Models 5:8102872
In: XX - C +9,05
Type - Material: <Unnamed>
Type - Other - Category: Generic Models; Family Name: Generic Models 5
Type - Identity Data - Type Name: Generic Models 5; Workset: XTA Terminal A
Constraints - Elevation from Level: 0 mm; Moves With Nearby Elements: no
Other - Family and Type: Generic Models 5: Generic Models 5; Type Id: 8102870; Family: Generic Models 5; Type: Generic Models 5
Dimensions - Area: 0.000722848 m2; Volume: 0.000738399 m3
Identity Data - TA Workset: yes; E203 TETT BYGG: yes; E204 INNVENDIGE: no
ePset_SimplebimBasicQuantities - Area, largest surface, net (Simplebim): 0.264904 m2; Length (Simplebim): 1021.5 mm; Height (Simplebim): 168.482 mm; Thickness (Simplebim): 132.197 mm; Volume, net (Simplebim): 0.000739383 m3
Pset_BuildingElementProxyCommon - Reference: Generic Models 5; sets with these values: 2
ePset_Simplebim - Assembly Level: Leaf
Phasing - Phase Created: Som Bygget
ePset_LocationTool - Splitting: ORIGINAL

# IfcBuildingElementProxy: Generic Models 6:Generic Models 6, Generic Models 6:Generic Models 6:8111694
In: XX - C +9,05
Type - Material: <Unnamed>
Type - Other - Category: Generic Models; Family Name: Generic Models 6
Type - Identity Data - Type Name: Generic Models 6; Workset: XTA Terminal A
Constraints - Elevation from Level: 0 mm; Moves With Nearby Elements: no
Other - Type Id: 8111692; Family and Type: Generic Models 6: Generic Models 6; Type: Generic Models 6; Family: Generic Models 6
Identity Data - TA Workset: yes; E203 TETT BYGG: yes; E204 INNVENDIGE: no
ePset_LocationTool - Splitting: ORIGINAL
ePset_SimplebimBasicQuantities - Height (Simplebim): 277.98 mm; Thickness (Simplebim): 12.2322 mm; Area, largest surface, net (Simplebim): 0.602043 m2; Volume, net (Simplebim): 0.00127134 m3; Length (Simplebim): 2165.78 mm
Pset_QuantityTakeOff - Reference: Generic Models 6; sets with these values: 2
ePset_Simplebim - Assembly Level: Leaf
Dimensions - Volume: 0.00127134 m3; Area: 0.000587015 m2
Phasing - Phase Created: Som Bygget

# IfcBuildingElementProxy: Hjørnedetalj-Sydøst7:Hjørnedetalj-Sydøst, Hjørnedetalj-Sydøst7:Hjørnedetalj-Sydøst:18203283
In: XX - C +9,05
Type - Material: _NSW Stål
Type - Other - Category: Generic Models; Family Name: Hjørnedetalj-Sydøst7
Type - Identity Data - Type Name: Hjørnedetalj-Sydøst; Workset: XTO Masterplan
ePset_LocationTool - Splitting: RESULT
Pset_QuantityTakeOff - Reference: Hjørnedetalj-Sydøst; sets with these values: 2
Identity Data - TA Workset: yes; E203 TETT BYGG: yes; E204 INNVENDIGE: no
Constraints - Moves With Nearby Elements: no
ePset_SimplebimBasicQuantities - Volume, net (Simplebim): 0.00113473 m3; Area, largest surface, net (Simplebim): 0.41401 m2; Thickness (Simplebim): 46 mm; Height (Simplebim): 125 mm; Length (Simplebim): 3366 mm
ePset_Simplebim - Assembly Level: Leaf
Phasing - Phase Created: Som Bygget
Other - Family and Type: Hjørnedetalj-Sydøst7: Hjørnedetalj-Sydøst; Type: Hjørnedetalj-Sydøst; Type Id: 18203281; Family: Hjørnedetalj-Sydøst7

# IfcBuildingElementProxy: V_TA Stål Facade Columns Type 1:V_TA Stål Facade Columns (3)
In: XX - C +9,05
Type - Material: _NSW Stål soyle
Type - Other - Category: Structural Framing; Family Name: V_TA Stål Facade Columns Type 1
Type - Constraints - Default Elevation: 1219.2 mm
Type - Identity Data - Type Name: V_TA Stål Facade Columns; Workset: Family : Structural Framing : V_TA Stål Facade Columns Type 1
Type - Dimensions - center: 40 mm; Material 1: 0 mm; width 1: 80 mm
Type - Materials and Finishes - Structural Material: _NSW Stål soyle
Type - Structural - Section Shape: 0
Identity Data - TA Workset: yes; Workset: XTO Masterplan
Constraints - Host: <not associated>
Pset_QuantityTakeOff - Reference: V_TA Stål Facade Columns; sets with these values: 2
ePset_LocationTool - Splitting: RESULT
ePset_Simplebim - Assembly Level: Leaf
Phasing - Phase Created: Som Bygget
Structural - Rebar Cover - Other Faces: Rebar Cover 1 <25 mm>; Rebar Cover - Bottom Face: Rebar Cover 1 <25 mm>; Rebar Cover - Top Face: Rebar Cover 1 <25 mm>
Other - Type Id: 776712; Family and Type: V_TA Stål Facade Columns Type 1: V_TA Stål Facade Columns; Family: V_TA Stål Facade Columns Type 1; Type: V_TA Stål Facade Columns
Name (V_TA Stål Facade Columns Type 1:V_TA Stål Facade Columns:...) | Height (Simplebim) (mm) | Length (Simplebim) (mm) | Volume, net (Simplebim) (m3) | Thickness (Simplebim) (mm) | Area, largest surface, net (Simplebim) (m2)
18202479 | 2384.9 | 2650.96 | 0.0240406 | 766.558 | 0.143099
18202480 | 2729.91 | 4097.35 | 0.143586 | 1504 | 0.572082
18202493 | 2816.27 | 4097.35 | 0.144457 | 1504 | 0.572082

# IfcBuildingElementProxy: V_TA Stål Facade Columns Type 1:V_TA Stål Facade Columns end, V_TA Stål Facade Columns Type 1:V_TA Stål Facade Columns end:18202576
In: XX - C +9,05
Type - Material: <Unnamed>
Type - Other - Category: Structural Framing; Family Name: V_TA Stål Facade Columns Type 1
Type - Constraints - Default Elevation: 1219.2 mm
Type - Identity Data - Type Name: V_TA Stål Facade Columns end; Workset: Family : Structural Framing : V_TA Stål Facade Columns Type 1
Type - Dimensions - center: 40 mm; Material 1: 0 mm; width 1: 80 mm
Type - Structural - Section Shape: 0
ePset_LocationTool - Splitting: RESULT
Other - Family: V_TA Stål Facade Columns Type 1; Type: V_TA Stål Facade Columns end; Type Id: 777869; Family and Type: V_TA Stål Facade Columns Type 1: V_TA Stål Facade Columns end
Identity Data - TA Workset: yes; Workset: XTO Masterplan
Constraints - Host: <not associated>
ePset_Simplebim - Assembly Level: Leaf
ePset_SimplebimBasicQuantities - Thickness (Simplebim): 1503.71 mm; Length (Simplebim): 4096.27 mm; Volume, net (Simplebim): 0.11635 m3; Area, largest surface, net (Simplebim): 0.571939 m2; Height (Simplebim): 139.995 mm
Phasing - Phase Created: Som Bygget
Pset_QuantityTakeOff - Reference: V_TA Stål Facade Columns end; sets with these values: 2
Structural - Rebar Cover - Other Faces: Rebar Cover 1 <25 mm>; Rebar Cover - Bottom Face: Rebar Cover 1 <25 mm>; Rebar Cover - Top Face: Rebar Cover 1 <25 mm>

# IfcBuildingElementProxy: V_TA Stål Facade Columns Type 3:V_TA Stål Facade Columns (2)
In: XX - C +9,05
Type - Material: _NSW Stål soyle
Type - Other - Category: Structural Framing; Family Name: V_TA Stål Facade Columns Type 3
Type - Constraints - Default Elevation: 1219.2 mm
Type - Identity Data - Type Name: V_TA Stål Facade Columns; Workset: Family : Structural Framing : V_TA Stål Facade Columns Type 3
Type - Dimensions - center: 20 mm; pipe: 80 mm
Type - Materials and Finishes - Structural Material: _NSW Stål soyle
Type - Structural - Section Shape: 0
ePset_SimplebimBasicQuantities - Area, largest surface, net (Simplebim): 0.519716 m2; Length (Simplebim): 4096.16 mm; Thickness (Simplebim): 1257.53 mm
Identity Data - TA Workset: yes; Workset: XTO Masterplan
Constraints - Host: <not associated>
Pset_QuantityTakeOff - Reference: V_TA Stål Facade Columns; sets with these values: 2
ePset_Simplebim - Assembly Level: Leaf
ePset_LocationTool - Splitting: RESULT
Phasing - Phase Created: Som Bygget
Structural - Rebar Cover - Other Faces: Rebar Cover 1 <25 mm>; Rebar Cover - Bottom Face: Rebar Cover 1 <25 mm>; Rebar Cover - Top Face: Rebar Cover 1 <25 mm>
Other - Family and Type: V_TA Stål Facade Columns Type 3: V_TA Stål Facade Columns; Family: V_TA Stål Facade Columns Type 3; Type: V_TA Stål Facade Columns; Type Id: 923139
Name (V_TA Stål Facade Columns Type 3:V_TA Stål Facade Columns:...) | Height (Simplebim) (mm) | Volume, net (Simplebim) (m3)
18202491 | 2693.55 | 0.0463521
18202492 | 2729.91 | 0.0467139

# IfcBuildingElementProxy: Værnes_Brannslange - integrert:3/110, Værnes_Brannslange - integrert:3/110:7588340
In: H01 Hovedetasje
Type - Material: Værnes Fire hose
Type - Other - Category: Specialty Equipment; Family Name: Værnes_Brannslange - integrert
Type - Constraints - Default Elevation: 0 mm
Type - Identity Data - Type Name: 3/110; Workset: Family : Specialty Equipment : Værnes_Brannslange - integrert
Type - Text - Equiptment Tag: BS01
Type - Dimensions - Depth: 110 mm; Height: 795 mm; Height above floor: 800 mm; Width: 795 mm
Type - Materials and Finishes - Material: Værnes Fire hose
ePset_SimplebimBasicQuantities - Length (Simplebim): 795 mm; Thickness (Simplebim): 111 mm; Volume, net (Simplebim): 0.0701548 m3; Height (Simplebim): 795 mm; Area, largest surface, net (Simplebim): 0.632025 m2
Identity Data - TA Workset: yes; E203 TETT BYGG: no; E204 INNVENDIGE: yes; Workset: XTA Terminal A
Dimensions - Area: 0.808515 m2; Volume: 0.0701548 m3
ePset_Simplebim - Assembly Level: Leaf
Pset_QuantityTakeOff - Reference: 3/110; sets with these values: 2
Other - Family: Værnes_Brannslange - integrert; Family and Type: Værnes_Brannslange - integrert: 3/110; Type: 3/110; Type Id: 6761704; Host Id: 5895648
Phasing - Phase Created: Som Bygget
ePset_LocationTool - Splitting: ORIGINAL
Constraints - Level: H01 Hovedetasje; Elevation from Level: 0 mm

# IfcBuildingElementProxy: Værnes_Søylebeskyttelse_E1_rustfritt stål:Værnes_Søylebeskyttelse_E1_rustfritt stål (2)
In: H01 Hovedetasje
Type - Material: <Unnamed>
Type - Other - Category: Specialty Equipment; Family Name: Værnes_Søylebeskyttelse_E1_rustfritt stål
Type - Constraints - Default Elevation: 0 mm
Type - Identity Data - Type Name: Værnes_Søylebeskyttelse_E1_rustfritt stål; Workset: Family : Specialty Equipment : Værnes_Søylebeskyttelse_E1_rustfritt stål
Type - Text - Equiptment Tag: CGS
Constraints - Level: H01 Hovedetasje; Host: Level : H01 Hovedetasje; Moves With Nearby Elements: no
Other - Family and Type: Værnes_Søylebeskyttelse_E1_rustfritt stål: Værnes_Søylebeskyttelse_E1_rustfritt stål; Type Id: 7370338; Family: Værnes_Søylebeskyttelse_E1_rustfritt stål; Type: Værnes_Søylebeskyttelse_E1_rustfritt stål
Identity Data - TA Workset: yes; E203 TETT BYGG: no; E204 INNVENDIGE: yes; Workset: XTA Terminal A
ePset_SimplebimBasicQuantities - Length (Simplebim): 732 mm; Height (Simplebim): 900 mm
ePset_Simplebim - Assembly Level: Leaf
Pset_BuildingElementProxyCommon - Reference: Værnes_Søylebeskyttelse_E1_rustfritt stål; sets with these values: 2
Phasing - Phase Created: Som Bygget
Name (Værnes_Søylebeskyttelse_E1_rustfritt stål:Værnes_Søylebeskyttelse_E1_rustfritt stål:...) | Splitting | Volume, net (Simplebim) (m3) | Area, largest surface, net (Simplebim) (m2) | Thickness (Simplebim) (mm)
7128235 | ORIGINAL | 0.00831166 | 1.60959 | 732 | Constraints - Elevation from Level: 0 mm; Offset from Host: 0 mm; Dimensions - Volume: 0.00835384 m3; Area: 1.79365 m2
7128234 | RESULT | 0.00415583 | 0.0911616 | 366

# IfcColumn: V_Betong+Stål Arms:400D x 8300mm +65deg/74deg (2)
In: H01 Hovedetasje
Type - PredefinedType: COLUMN; Material: NO_Betong
Type - Other - Category: Columns; Family Name: V_Betong+Stål Arms
Type - Dimensions - Diameter: 400 mm; Column Height: 8300 mm; Radius: 200 mm; Width: 400 mm; Arm Angle 1: 74 deg; Arm Angle 2: 65.2 deg; Stål Arm length 1: 2000 mm; Stål Arm Length 2: 1850 mm
Type - Graphics - Coarse Scale Fill Color: 0
Type - Identity Data - Type Name: 400D x 8300mm +65deg/74deg; Workset: Family : Columns : V_Betong+Stål Arms; OmniClass Number: 23.25.30.11.14.11; OmniClass Title: Columns
Type - Pset_ColumnCommon - IsExternal: no
Type - Materials and Finishes - Column: NO_Betong
ePset_LocationTool - Splitting: RESULT
Pset_ReinforcementBarPitchOfColumn - Reference: 400D x 8300mm +65deg/74deg; sets with these values: 2
Other - Family: V_Betong+Stål Arms; Type Id: 321136; Family and Type: V_Betong+Stål Arms: 400D x 8300mm +65deg/74deg; Type: 400D x 8300mm +65deg/74deg
Pset_ColumnCommon - Reference: 400D x 8300mm +65deg/74deg
ePset_SimplebimBasicQuantities - Volume, net (Simplebim): 0.500107 m3; Area, sides, net (Simplebim): 5.02017 m2; Width (Simplebim): 400 mm; Depth (Simplebim): 400 mm; Height (Simplebim): 4000 mm; Weight, as steel (Simplebim): 3925.84 kg
Identity Data - TA Workset: yes; Workset: XTO Masterplan
Constraints - Level: H01 Hovedetasje; Base Level: H01 Hovedetasje; Moves With Grids: yes; Room Bounding: yes; Top Level: XX - C +15,37 TA E2
ePset_Simplebim - Assembly Level: Leaf
Phasing - Phase Created: Som Bygget
Name (V_Betong+Stål Arms:400D x 8300mm +65deg/74deg:...)
18202448
18202450

# IfcColumn: Værnes I Beam Fasade Vert:Værnes I Beam Fasade Vert, Værnes I Beam Fasade Vert:Værnes I Beam Fasade Vert:5607447
In: H01 Hovedetasje
Type - PredefinedType: COLUMN; Material: Værnes_Stål
Type - Other - Category: Structural Columns; Family Name: Værnes I Beam Fasade Vert; Depth: 500 mm; Width: 500 mm
Type - Identity Data - Type Name: Værnes I Beam Fasade Vert; Workset: Family : Structural Columns : Værnes I Beam Fasade Vert; OmniClass Number: 23.25.30.11.14.11; OmniClass Title: Columns
Type - Pset_ColumnCommon - IsExternal: no; LoadBearing: yes
Type - Materials and Finishes - Structural Material: Værnes_Stål
Type - Structural - Section Shape: 0
Construction - Top Cut Style: Perpendicular; Base Cut Style: Perpendicular
Constraints - Level: H01 Hovedetasje; Base Level: H01 Hovedetasje; Column Style: Slanted - Angle Driven; Top Level: XX - C +09,60 Hotel L1; Move Top With Grids: yes; Move Base With Grids: yes
Pset_ColumnCommon - Reference: Værnes I Beam Fasade Vert
Pset_QuantityTakeOff - Reference: Værnes I Beam Fasade Vert; sets with these values: 2
Other - Type Id: 4950427; Family and Type: Værnes I Beam Fasade Vert: Værnes I Beam Fasade Vert; Type: Værnes I Beam Fasade Vert; Family: Værnes I Beam Fasade Vert
ePset_LocationTool - Splitting: RESULT
Structural - Rebar Cover - Other Faces: Rebar Cover 1 <25 mm>
ePset_Simplebim - Assembly Level: Leaf
ePset_SimplebimBasicQuantities - Weight, as steel (Simplebim): 181.263 kg; Width (Simplebim): 220 mm; Depth (Simplebim): 1182 mm; Height (Simplebim): 4014 mm; Volume, net (Simplebim): 0.0230908 m3; Area, sides, net (Simplebim): 3.52822 m2
Phasing - Phase Created: Som Bygget
Identity Data - Workset: TA-TC - Struktur; E203 TETT BYGG: yes; E204 INNVENDIGE: no; Has Association: yes

# IfcColumn: Værnes_Søyle med Krone_Syd:500D x 8210mm, Værnes_Søyle med Krone_Syd:500D x 8210mm:5100128
In: H01 Hovedetasje
Type - PredefinedType: COLUMN; Material: Værnes_Concrete column
Type - Other - Category: Columns; Family Name: Værnes_Søyle med Krone_Syd
Type - Dimensions - Diameter: 500 mm; Column Height: 8210 mm; Radius: 250 mm; Width: 500 mm
Type - Graphics - Coarse Scale Fill Color: 0
Type - Identity Data - Type Name: 500D x 8210mm; Workset: Family : Columns : Værnes_Søyle med Krone_Syd; OmniClass Number: 23.25.30.11.14.11; OmniClass Title: Columns
Type - Pset_ColumnCommon - IsExternal: no
Type - Materials and Finishes - Column: Værnes_Concrete column
ePset_SimplebimBasicQuantities - Weight, as steel (Simplebim): 4020.04 kg; Width (Simplebim): 500 mm; Depth (Simplebim): 500 mm; Height (Simplebim): 4000 mm; Volume, net (Simplebim): 0.512107 m3
Other - Family: Værnes_Søyle med Krone_Syd; Type Id: 5102167; Type: 500D x 8210mm; Family and Type: Værnes_Søyle med Krone_Syd: 500D x 8210mm
Visibility - N/R BIM do not use: yes
Pset_ColumnCommon - Reference: 500D x 8210mm
ePset_Simplebim - Assembly Level: Leaf
Pset_QuantityTakeOff - Reference: 500D x 8210mm; sets with these values: 2
ePset_LocationTool - Splitting: RESULT
Phasing - Phase Created: Som Bygget
Identity Data - Workset: TA-TC - Struktur; TA Workset: yes; E203 TETT BYGG: no; E204 INNVENDIGE: no
Constraints - Level: H01 Hovedetasje; Base Level: H01 Hovedetasje; Top Level: XX - C +09,60 Hotel L1; Moves With Grids: yes; Room Bounding: yes

# IfcCovering: Compound Ceiling:Værnes Himling H-GIPS 01, Compound Ceiling:Værnes Himling H-GIPS 01:13148421
In: H01 Hovedetasje
Type - PredefinedType: CEILING
Type - Other - Category: Ceilings; Family Name: Compound Ceiling
Type - Construction - Thickness: 83 mm
Type - Graphics - Coarse Scale Fill Color: 0
Type - Identity Data - Type Name: Værnes Himling H-GIPS 01; Workset: Ceiling Types
Type - Text - Himling Kode: H-GIPS 01
Type - Analytical Properties - Roughness: 1; Absorptance: 0.1
Type - Pset_CoveringCommon - TotalThickness: 83 mm
Identity Data - TA Workset: yes; Workset: XTA Terminal A
Pset_CoveringCommon - Finish: Værnes_Gips Himling;; Reference: Værnes Himling H-GIPS 01
ePset_SimplebimBasicQuantities - Volume, net (Simplebim): 7.37898 m3; Area, largest surface, net (Simplebim): 88.9034 m2; Height (Simplebim): 83 mm; Width (Simplebim): 7889 mm; Length (Simplebim): 13581 mm
ePset_Simplebim - Assembly Level: Leaf
Phasing - Phase Created: Som Bygget
ePset_LocationTool - Splitting: RESULT
Other - Family: Compound Ceiling; Type Id: 5253817; Type: Værnes Himling H-GIPS 01; Family and Type: Compound Ceiling: Værnes Himling H-GIPS 01
Constraints - Level: H01 Hovedetasje; Room Bounding: yes
Pset_QuantityTakeOff - Reference: Værnes Himling H-GIPS 01

# IfcCurtainWall: Curtain System:1500 x 3000, Curtain System:1500 x 3000:3065420
In: H01 Hovedetasje
Type - Other - Category: Curtain Systems; Family Name: Curtain System
Type - Construction - Join Condition: Not Defined
Type - Identity Data - Type Name: 1500 x 3000; Workset: Curtain System Types
Type - Grid 1 - Adjust for Mullion Size: no; Layout: Fixed Distance; Spacing: 3000 mm
Type - Grid 2 - Adjust for Mullion Size: no; Layout: Fixed Distance; Spacing: 1500 mm
Type - Pset_CurtainWallCommon - IsExternal: no
Constraints - Related to Mass: no; Room Bounding: yes
Pset_CurtainWallCommon - Reference: 1500 x 3000
Pset_QuantityTakeOff - Reference: 1500 x 3000
Identity Data - Workset: XTA Terminal A
ePset_SimplebimBasicQuantities - Width: 3025.16 mm; Length: 71100 mm; Volume, net (Simplebim): 36.9614 m3; Height: 10402.7 mm
ePset_Simplebim - Assembly Level: Topmost
Other - Type: 1500 x 3000; Family: Curtain System; Type Id: 49034; Family and Type: Curtain System: 1500 x 3000
Phasing - Phase Created: Som Bygget
Grid 2 - Number: 4; Angle: 0 deg; Offset: 0 mm; Justification: Beginning
Grid 1 - Angle: 0 deg; Offset: 0 mm; Number: 4; Justification: Beginning

# IfcCurtainWall: Curtain System:2700 x 1790, Curtain System:2700 x 1790:18203014
In: H01 Hovedetasje
Type - Other - Category: Curtain Systems; Family Name: Curtain System
Type - Construction - Join Condition: Not Defined
Type - Identity Data - Type Name: 2700 x 1790; Workset: Curtain System Types
Type - Grid 1 - Adjust for Mullion Size: no; Layout: Fixed Distance; Spacing: 2700 mm
Type - Grid 2 - Adjust for Mullion Size: no; Layout: Fixed Distance; Spacing: 1790 mm
Type - Pset_CurtainWallCommon - IsExternal: no
Constraints - Related to Mass: no; Room Bounding: yes
ePset_SimplebimBasicQuantities - Length: 70828.1 mm; Height: 9545.06 mm; Width: 2627.92 mm; Volume, net (Simplebim): 26.0214 m3
Identity Data - TA Workset: yes; Workset: XTO Masterplan
ePset_Simplebim - Assembly Level: Topmost
Other - Type: 2700 x 1790; Family: Curtain System; Type Id: 4731579; Family and Type: Curtain System: 2700 x 1790
Phasing - Phase Created: Som Bygget
Pset_QuantityTakeOff - Reference: 2700 x 1790
Pset_CurtainWallCommon - Reference: 2700 x 1790
Grid 2 - Number: 4; Angle: 0 deg; Offset: 0 mm; Justification: Beginning
Grid 1 - Angle: 0 deg; Offset: 0 mm; Number: 4; Justification: Beginning

# IfcCurtainWall: Curtain Wall:V_TA Curtain Wall Solid panels, Curtain Wall:V_TA Curtain Wall Solid panels:5660698
In: H01 Hovedetasje
Type - Other - Category: Walls; Family Name: Curtain Wall
Type - Construction - Join Condition: Not Defined; Function: Exterior; Automatically Embed: no
Type - Identity Data - Type Name: V_TA Curtain Wall Solid panels; Workset: Curtain Wall Types
Type - Pset_CurtainWallCommon - IsExternal: yes
Type - Horizontal Grid - Adjust for Mullion Size: no
Type - Vertical Grid - Adjust for Mullion Size: no
Pset_QuantityTakeOff - Reference: V_TA Curtain Wall Solid panels
Identity Data - TA Workset: yes; E203 TETT BYGG: yes; E204 INNVENDIGE: no; Workset: XTA Terminal A
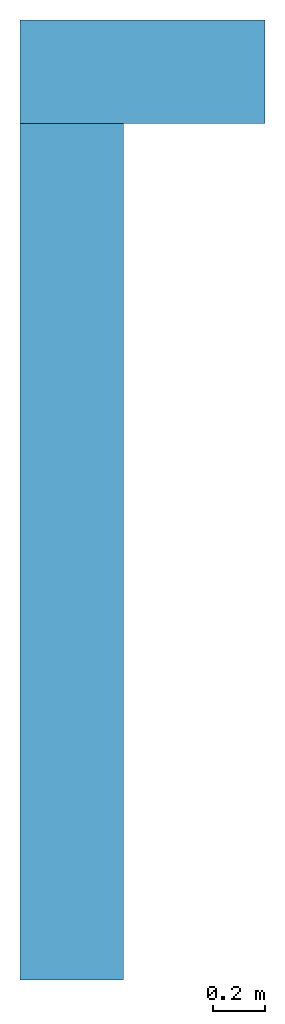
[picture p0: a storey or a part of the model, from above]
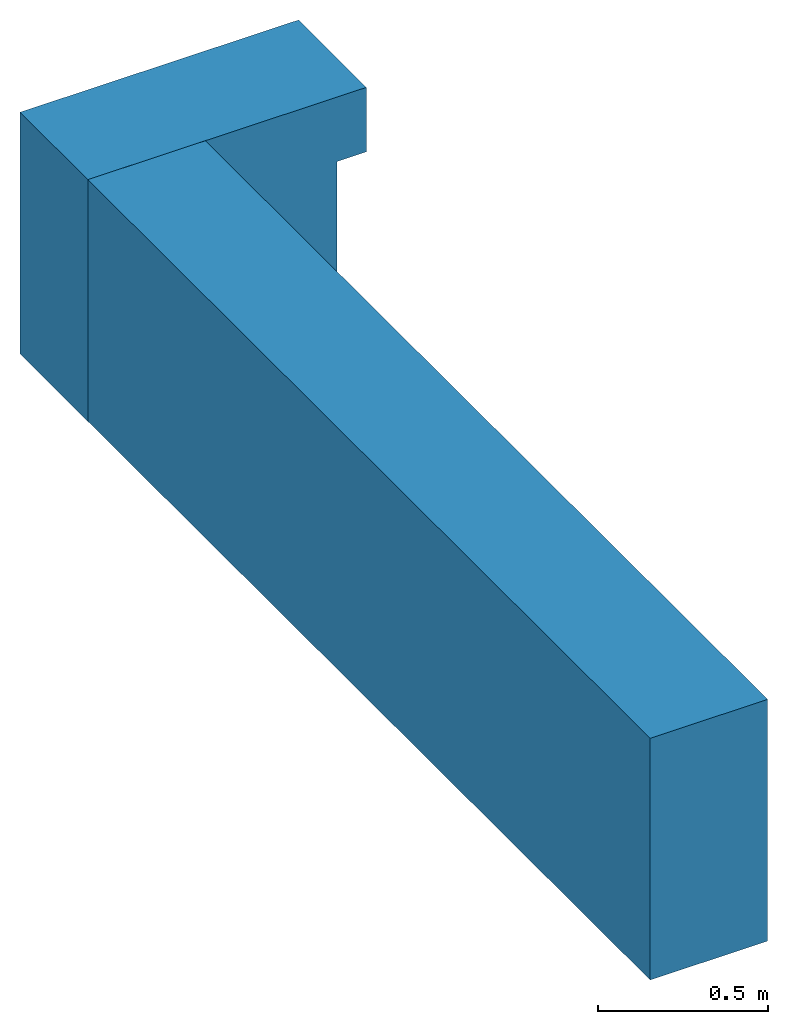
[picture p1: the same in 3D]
Properties of the parts of a building model (IFC2X3), part 2 of 3

# IfcCurtainWall: Curtain Wall:V_TA Curtain Wall Solid panels, Curtain Wall:V_TA Curtain Wall Solid panels:5660698
Structural - Structural Usage: Non-bearing; Structural: no
ePset_Simplebim - Assembly Level: Topmost
Dimensions - Length: 7945.45 mm; Area: 34.7216 m2
Cross-Section Definition - Cross-Section: Vertical
ePset_SimplebimBasicQuantities - Height: 9725.84 mm; Length: 6132.44 mm; Width: 238.966 mm; Volume, net (Simplebim): 2.24734 m3
Phasing - Phase Created: Som Bygget
Pset_CurtainWallCommon - Reference: V_TA Curtain Wall Solid panels
Horizontal Grid - Number: 4; Angle: 0 deg; Offset: 0 mm; Justification: Beginning
Vertical Grid - Angle: 0 deg; Offset: 0 mm; Number: 4; Justification: Beginning
Constraints - Top Constraint: Up to level: XX - C +09,60 Hotel L1; Base Constraint: H01 Hovedetasje; Top Offset: 10343.6 mm; Unconnected Height: 10623.6 mm; Related to Mass: no; Room Bounding: yes; Base is Attached: no; Top is Attached: no; Base Offset: 0 mm
Other - Family and Type: Curtain Wall: V_TA Curtain Wall Solid panels; Type: V_TA Curtain Wall Solid panels; Kontor Blokk innervegg: no; Family: Curtain Wall; Type Id: 5659901

# IfcDoor: Værnes_DB INT-Tilkomst Luke_Stål:600x600mm 600mm OFG, Værnes_DB INT-Tilkomst Luke_Stål:600x600mm 600mm OFG:6851109
In: H01 Hovedetasje
Type - ParameterTakesPrecedence: no; Sizeable: no; Material: Door - Frame, Door - Panel
Type - Other - Category: Doors; Family Name: Værnes_DB INT-Tilkomst Luke_Stål
Type - Construction - Function: Interior; Wall Closure: By host
Type - Dimensions - Height: 0 mm; Width: 600 mm; Door cill height above FFL: 600 mm; Door head height above FFL: 1200 mm; Thickness: 50 mm; Trim Projection Ext: 25 mm; Trim Projection Int: 25 mm; Trim Width: 50 mm
Type - Identity Data - NTI_QuantityDoorSwingLeft: 1; NTI_QuantityDoorSwingRight: 0; Type Mark: 200; Type Name: 600x600mm 600mm OFG; Workset: Family : Doors : Værnes_DB INT-Tilkomst Luke_Stål; OmniClass Number: 23.30.10.00; OmniClass Title: Doors
Type - Analytical Properties - Define Thermal Properties by: Schematic Type; Analytic Construction: <None>
Type - Pset_DoorCommon - IsExternal: no
Type - Materials and Finishes - Door Material: Door - Panel; Frame Material: Door - Frame
OverallHeight: 600 mm; OverallWidth: 600 mm
Dimensions - Area: 0.84 m2; Volume: 0.0245 m3
Materials and Finishes - Finish: Malt RAL 7037; Dørblad: Stål; Frame Material: Stål
ePset_SimplebimBasicQuantities - Area (Simplebim): 0.49 m2; Width (Simplebim): 700 mm; Height (Simplebim): 700 mm; Length, frame (Simplebim): 2100 mm
Identity Data - Romnummer_dør: 1.636 SJAKT; TA Workset: yes; E203 TETT BYGG: no; E204 INNVENDIGE: yes; Mark: TAE1L.30; NTI_DoorSwing: L; NTI_DoorType: I; NTI_HostWallWidth: 186 mm; Workset: XTA Terminal A
Other - Type Id: 6767261; Type: 600x600mm 600mm OFG; Host Id: 5895036; Head Height: 299.267 mm; Family and Type: Værnes_DB INT-Tilkomst Luke_Stål: 600x600mm 600mm OFG; Family: Værnes_DB INT-Tilkomst Luke_Stål
Pset_DoorCommon - Reference: 600x600mm 600mm OFG
Pset_QuantityTakeOff - Reference: 600x600mm 600mm OFG
Phasing - Phase Created: Som Bygget
Text - Dør Overflate: Malt RAL7037; Dør Kode: 6X6M; Entreprisenummer: E204; Karmtykkelse_dør: std; Slagretning: 2FL
General - Dør Lås: Sylindere
ePset_LocationTool - Splitting: ORIGINAL
ePset_Simplebim - Assembly Level: Leaf
Constraints - Level: H01 Hovedetasje; Sill Height: 299.267 mm

# IfcDoor: Værnes_ENK INT-Dørblad laminert_ Ramme stål:700 x 2100mm, Værnes_ENK INT-Dørblad laminert_ Ramme stål:700 x 2100mm:6848228
In: H01 Hovedetasje
Type - OperationType: SINGLE_SWING_RIGHT; ParameterTakesPrecedence: no; Sizeable: no; Material: N_Door - Handle
Type - IfcDoorPanelProperties - PanelOperation: SWINGING
Type - Other - Category: Doors; Family Name: Værnes_ENK INT-Dørblad laminert_ Ramme stål
Type - Construction - Function: Interior; Wall Closure: By host
Type - Dimensions - Frame Depth: 92 mm; Frame Thickness: 42 mm; Height: 2090 mm; Width: 700 mm
Type - Identity Data - NTI_QuantityDoorSwingLeft: 1; NTI_QuantityDoorSwingRight: 0; Type Mark: 375; Type Name: 700 x 2100mm; Workset: Family : Doors : Værnes_ENK INT-Dørblad laminert_ Ramme stål
Type - Analytical Properties - Define Thermal Properties by: Schematic Type; Analytic Construction: <None>
Type - Pset_DoorCommon - IsExternal: no
OverallHeight: 2100 mm; OverallWidth: 720 mm
Pset_DoorCommon - Reference: 700 x 2100mm
Dimensions - Volume: 0.0694096 m3; Area: 2.08076 m2; Placement: 0 mm; Joint: 10 mm; Joint Threshold: 10 mm
Identity Data - Mark: TAE1L.29; Romnummer_dør: 1.635 SJAKT; TA Workset: yes; E203 TETT BYGG: no; E204 INNVENDIGE: yes; NTI_DoorSwing: L; NTI_DoorType: I; NTI_HostWallWidth: 186 mm; Workset: XTA Terminal A
Phasing - Phase Created: Som Bygget
Text - Dør Overflate: Laminat RAL7037; Entreprisenummer: E204; Karmtykkelse_dør: std; Slagretning: V; Dør Kode: 7x21M
Other - Type Id: 13001626; Type: 700 x 2100mm; Host Id: 11590759; Family and Type: Værnes_ENK INT-Dørblad laminert_ Ramme stål: 700 x 2100mm; Family: Værnes_ENK INT-Dørblad laminert_ Ramme stål; Head Height: 2090 mm
ePset_SimplebimBasicQuantities - Area (Simplebim): 1.456 m2; Area, opening (Simplebim): 1.512 m2; Width (Simplebim): 700 mm; Width, opening (Simplebim): 720 mm; Height, opening (Simplebim): 2100 mm; Height (Simplebim): 2080 mm; Length, frame (Simplebim): 4860 mm
ePset_LocationTool - Splitting: ORIGINAL
ePset_Simplebim - Assembly Level: Leaf
Pset_QuantityTakeOff - Reference: 700 x 2100mm
General - Dør Lås: Sylindere; Kommentarer: Inspeksjonsluk
Constraints - Level: H01 Hovedetasje; Sill Height: 0 mm
Materials and Finishes - Dørblad: Massiv; Finish: Malt RAL 7037; Frame Material: Stål

# IfcFlowTerminal: Værnes_Lysarmatur_gulv_B:UP17 (2)
In: H01 Hovedetasje
Type - Material: <Unnamed>
Type - Other - Category: Lighting Fixtures; Family Name: Værnes_Lysarmatur_gulv_B
Type - Constraints - Default Elevation: 0 mm
Type - Identity Data - Beskrivelse: http://www.deltalight.com/#/products/product/8068/; OmniClass Number: 23.80.70.00; OmniClass Title: Lighting; Product name: deltalight tactic 4R ..213 44 14; Type Name: UP17; Workset: Family : Lighting Fixtures : Værnes_Lysarmatur_gulv_B
Type - Text - Lys Kode: UP17
Other - Type: UP17; Family and Type: Værnes_Lysarmatur_gulv_B: UP17; Family: Værnes_Lysarmatur_gulv_B; Type Id: 6474191
Constraints - Level: H01 Hovedetasje; Host: Level : H01 Hovedetasje; Offset from Host: -170 mm; Elevation from Level: -170 mm; Moves With Nearby Elements: no
ePset_LocationTool - Splitting: ORIGINAL
Pset_QuantityTakeOff - Reference: UP17; sets with these values: 2
Phasing - Phase Created: Som Bygget
Electrical - Lighting - Calculate Coefficient of Utilization: no
Identity Data - TA Workset: yes; E203 TETT BYGG: no; E204 INNVENDIGE: yes; Workset: XTA Terminal A
ePset_Simplebim - Assembly Level: Leaf
Dimensions - Volume: 0.000413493 m3; Area: 0.01555 m2
Name (Værnes_Lysarmatur_gulv_B:UP17:...) | Mark
6474251 | 790
6474252 | 791

# IfcFlowTerminal: Værnes_Lysarmatur_søyle_D trail NORD:UP 16, Værnes_Lysarmatur_søyle_D trail NORD:UP 16:11397457
In: XX - C +7,57 TB U1
Type - Material: BEGA-UP-LIGHT
Type - Other - Category: Lighting Fixtures; Family Name: Værnes_Lysarmatur_søyle_D trail NORD
Type - Constraints - Default Elevation: 0 mm
Type - Identity Data - OmniClass Number: 23.80.70.00; OmniClass Title: Lighting; Type Name: UP 16; Workset: Family : Lighting Fixtures : Værnes_Lysarmatur_søyle_D trail NORD
Type - Text - Lys Kode: UP16
Type - Dimensions - Bredde: 220 mm; height from floor: 3485.65 mm; Lengde: 485 mm; Light Source Symbol Length: 3048 mm; UK HØYDE: 5000 mm
Type - Photometrics - Color Filter: 16777215; Dimming Lamp Color Temperature Shift: <None>; Efficacy: 150.54; Illuminance: 2748.8; Initial Color: 0; Initial Color Temperature: 3200; Initial Intensity: 0; Light Loss Factor: 0; Light Source Definition (family): Point+Spot; Luminous Flux: 7527; Luminous Intensity: 25537.2; Spot Beam Angle: 60 deg; Spot Field Angle: 80 deg; Tilt Angle: 130 deg; Total Light Loss Factor: 1; Wattage: 50 W
Type - Materials and Finishes - Material: BEGA-UP-LIGHT
Pset_QuantityTakeOff - Reference: UP 16; sets with these values: 2
Identity Data - TA Workset: yes; Workset: XTA Terminal A; Mark: 1738
Other - Family: Værnes_Lysarmatur_søyle_D trail NORD; Type Id: 12058680; Family and Type: Værnes_Lysarmatur_søyle_D trail NORD: UP 16; Type: UP 16
ePset_LocationTool - Splitting: ORIGINAL
Phasing - Phase Created: Som Bygget
Constraints - Moves With Nearby Elements: no; Level: XX - C +7,57 TB U1; Host: Level : XX - C +7,57 TB U1; Offset from Host: 2250 mm; Elevation from Level: 2250 mm
Electrical - Lighting - Calculate Coefficient of Utilization: no
Dimensions - Area: 41.0082 m2; Volume: 30.7706 m3
ePset_Simplebim - Assembly Level: Leaf

# IfcFlowTerminal: Værnes_Lysarmatur_søyle_D trail SOUTH:UP 16, Værnes_Lysarmatur_søyle_D trail SOUTH:UP 16:11397458
In: XX - C +7,57 TB U1
Type - Material: BEGA-UP-LIGHT
Type - Other - Category: Lighting Fixtures; Family Name: Værnes_Lysarmatur_søyle_D trail SOUTH
Type - Constraints - Default Elevation: 0 mm
Type - Identity Data - OmniClass Number: 23.80.70.00; OmniClass Title: Lighting; Type Name: UP 16; Workset: Family : Lighting Fixtures : Værnes_Lysarmatur_søyle_D trail SOUTH
Type - Text - Lys Kode: UP16
Type - Dimensions - Bredde: 220 mm; height from floor: 3485.65 mm; Lengde: 485 mm; Light Source Symbol Length: 3048 mm; UK HØYDE: 5000 mm
Type - Photometrics - Color Filter: 16777215; Dimming Lamp Color Temperature Shift: <None>; Efficacy: 150.54; Illuminance: 2748.8; Initial Color: 0; Initial Color Temperature: 3200; Initial Intensity: 0; Light Loss Factor: 0; Light Source Definition (family): Point+Spot; Luminous Flux: 7527; Luminous Intensity: 25537.2; Spot Beam Angle: 60 deg; Spot Field Angle: 80 deg; Tilt Angle: 130 deg; Total Light Loss Factor: 1; Wattage: 50 W
Type - Materials and Finishes - Material: BEGA-UP-LIGHT
Pset_QuantityTakeOff - Reference: UP 16; sets with these values: 2
Identity Data - Mark: 1739; TA Workset: yes; Workset: XTA Terminal A
Dimensions - Volume: 30.7706 m3; Area: 41.0151 m2
Phasing - Phase Created: Som Bygget
ePset_LocationTool - Splitting: ORIGINAL
Constraints - Moves With Nearby Elements: no; Level: XX - C +7,57 TB U1; Host: Level : XX - C +7,57 TB U1; Offset from Host: 2250 mm; Elevation from Level: 2250 mm
Electrical - Lighting - Calculate Coefficient of Utilization: no
ePset_Simplebim - Assembly Level: Leaf
Other - Family: Værnes_Lysarmatur_søyle_D trail SOUTH; Type Id: 12058590; Family and Type: Værnes_Lysarmatur_søyle_D trail SOUTH: UP 16; Type: UP 16

# IfcMember: Rectangular Mullion:Værnes 50 X 150 Fasade TA (9)
In: H01 Hovedetasje
Type - PredefinedType: MULLION; Material: T2_Metal_Aluminium
Type - Other - Category: Curtain Wall Mullions; Family Name: Rectangular Mullion
Type - Constraints - Angle: 0 deg; Offset: 0 mm
Type - Construction - Corner Mullion: no; Position: Perpendicular to Face; Profile: NSW_Mullion Fasade : P_Mullion Fasade; Thickness: 238.966 mm
Type - Dimensions - Width on side 1: 25 mm; Width on side 2: 25 mm
Type - Identity Data - Type Name: Værnes 50 X 150 Fasade TA; Workset: Family : Curtain Wall Mullions : Rectangular Mullion
Type - Materials and Finishes - Material: T2_Metal_Aluminium
Type - Pset_MemberCommon - IsExternal: no
Pset_QuantityTakeOff - Reference: Værnes 50 X 150 Fasade TA
Pset_MemberCommon - Reference: Værnes 50 X 150 Fasade TA
Identity Data - TA Workset: yes; E203 TETT BYGG: yes; E204 INNVENDIGE: no; Workset: XTA Terminal A
Phasing - Phase Created: Som Bygget
Other - Family: Rectangular Mullion; Type Id: 4734683; Family and Type: Rectangular Mullion: Værnes 50 X 150 Fasade TA; Type: Værnes 50 X 150 Fasade TA; Host Id: 5660698
ePset_Simplebim - Assembly Level: Leaf
Constraints - Level: H01 Hovedetasje
Name (Rectangular Mullion:Værnes 50 X 150 Fasade TA:...) | Area (m2) | Volume (m3) | Length (mm) = Span (mm) | Splitting | Area, sides, net (Simplebim) (m2) | Weight, as steel (Simplebim) (kg) | Volume, net (Simplebim) (m3) | Width (Simplebim) (mm) | Height (Simplebim) (mm) | Length (Simplebim) (mm)
7958523 | 0.683509 | 0.0277593 | 2375.05 | ORIGINAL | 1.36702 | 217.91 | 0.0277593 | 238.966 | 50 | 2329.99
7958524 | 0.817409 | 0.0332958 | 2838.43 | ORIGINAL | 1.63482 | 261.372 | 0.0332958 | 238.966 | 50 | 2793.36
7958534 | 0.51157 | 0.0206586 | 1729 | ORIGINAL | 1.02314 | 162.17 | 0.0206586 | 50 | 1729 | 238.966
7958535 | 0.511624 | 0.0206608 | 1729.19 | ORIGINAL | 1.02314 | 162.17 | 0.0206586 | 50 | 1729 | 238.966
7958536 | 0.26855 | 0.0106101 | 888 | ORIGINAL | 0.537099 | 83.289 | 0.0106101 | 50 | 888 | 238.966
8084622 | 0.895351 | 0.0363686 | 3076.42 | ORIGINAL | 1.7907 | 285.493 | 0.0363686 | 238.966 | 50 | 3076.42
8103430 | 0.529201 | 0.0213876 | 1790.02 | ORIGINAL | 1.0584 | 167.893 | 0.0213876 | 50 | 1790.02 | 238.966
8103431 | 0.27203 | 0.0105952 | 919.338 | ORIGINAL | 0.54406 | 83.1723 | 0.0105952 | 50 | 919.338 | 238.966
8103433 |  |  |  | RESULT | 0.885467 | 139.758 | 0.0178036 | 50 | 1497 | 238

# IfcMember: Rectangular Mullion:Værnes 50 x 56 (24)
In: H01 Hovedetasje
Type - PredefinedType: MULLION; Material: T2_Metal_Aluminium
Type - Other - Category: Curtain Wall Mullions; Family Name: Rectangular Mullion
Type - Constraints - Angle: 0 deg; Offset: 0 mm
Type - Construction - Corner Mullion: no; Position: Perpendicular to Face; Profile: Værnes_Rail profile : P_Rail profile Værnes; Thickness: 60 mm
Type - Dimensions - Width on side 1: 28 mm; Width on side 2: 28 mm
Type - Identity Data - Type Name: Værnes 50 x 56; Workset: Family : Curtain Wall Mullions : Rectangular Mullion
Type - Materials and Finishes - Material: T2_Metal_Aluminium
Type - Pset_MemberCommon - IsExternal: no
Other - Family: Rectangular Mullion; Type Id: 2562502; Family and Type: Rectangular Mullion: Værnes 50 x 56; Type: Værnes 50 x 56
Pset_QuantityTakeOff - Reference: Værnes 50 x 56
Pset_MemberCommon - Reference: Værnes 50 x 56
Phasing - Phase Created: Som Bygget
ePset_Simplebim - Assembly Level: Leaf
Name (Rectangular Mullion:Værnes 50 x 56:...) | Host Id | Splitting | Span (mm) = Length (mm) | Workset | Weight, as steel (Simplebim) (kg) | Area, sides, net (Simplebim) (m2) | Width (Simplebim) (mm) | Height (Simplebim) (mm) | Volume, net (Simplebim) (m3) | Length (Simplebim) (mm) | Area (m2) | Volume (m3)
3065698 | 3065420 | ORIGINAL | 2644 | XTA Terminal A | 69.7381 | 0.620128 | 60 | 56 | 0.00888384 | 2644 | 0.310064 | 0.00888384
3065701 | 3065420 | ORIGINAL | 2700 | XTA Terminal A | 71.2152 | 0.63312 | 60 | 56 | 0.009072 | 2700 | 0.31656 | 0.009072
3065702 | 3065420 | ORIGINAL | 2672 | XTA Terminal A | 70.4767 | 0.626624 | 60 | 56 | 0.00897792 | 2672 | 0.313312 | 0.00897792
3065703 | 3065420 | ORIGINAL | 2644 | XTA Terminal A | 69.7381 | 0.620128 | 60 | 56 | 0.00888384 | 2644 | 0.310064 | 0.00888384
3065706 | 3065420 | ORIGINAL | 2681.73 | XTA Terminal A | 70.7334 | 0.628882 | 60 | 56 | 0.00901062 | 2681.73 | 0.314441 | 0.00901062
3065709 | 3065420 | ORIGINAL | 440.267 | XTA Terminal A | 11.6125 | 0.108862 | 60 | 56 | 0.0014793 | 440.267 | 0.054431 | 0.0014793 | Identity Data - TA Workset: yes
3065734 | 3065420 | ORIGINAL | 2672 | XTA Terminal A | 70.4767 | 0.626624 | 60 | 56 | 0.00897792 | 2672 | 0.313312 | 0.00897792
3065735 | 3065420 | ORIGINAL | 2644 | XTA Terminal A | 69.7381 | 0.620128 | 60 | 56 | 0.00888384 | 2644 | 0.310064 | 0.00888384
3065736 | 3065420 | ORIGINAL | 2700 | XTA Terminal A | 71.2152 | 0.63312 | 60 | 56 | 0.009072 | 2700 | 0.31656 | 0.009072
3065738 | 3065420 | ORIGINAL | 2644 | XTA Terminal A | 69.7381 | 0.620128 | 60 | 56 | 0.00888384 | 2644 | 0.310064 | 0.00888384
3065739 | 3065420 | ORIGINAL | 2681.73 | XTA Terminal A | 70.7334 | 0.628882 | 60 | 56 | 0.00901062 | 2681.73 | 0.314441 | 0.00901062
3065744 | 3065420 | ORIGINAL | 440.267 | XTA Terminal A | 11.6125 | 0.108862 | 60 | 56 | 0.0014793 | 440.267 | 0.054431 | 0.0014793 | Identity Data - TA Workset: yes
3065864 | 3065420 | ORIGINAL | 980 | XTA Terminal A | 25.8485 | 0.23408 | 56 | 980 | 0.0032928 | 60 | 0.11704 | 0.0032928
3065869 | 3065420 | ORIGINAL | 1795 | XTA Terminal A | 47.3449 | 0.42316 | 56 | 1795 | 0.0060312 | 60 | 0.21158 | 0.0060312
3065871 | 3065420 | ORIGINAL | 980 | XTA Terminal A | 25.8485 | 0.23408 | 56 | 980 | 0.0032928 | 60 | 0.11704 | 0.0032928
3065874 | 3065420 | ORIGINAL | 1795 | XTA Terminal A | 47.3449 | 0.42316 | 56 | 1795 | 0.0060312 | 60 | 0.21158 | 0.0060312
3065878 | 3065420 | ORIGINAL | 980 | XTA Terminal A | 25.8485 | 0.23408 | 56 | 980 | 0.0032928 | 60 | 0.11704 | 0.0032928
3065880 | 3065420 | ORIGINAL | 1795 | XTA Terminal A | 47.3449 | 0.42316 | 56 | 1795 | 0.0060312 | 60 | 0.21158 | 0.0060312
18203381 | 18203014 | ORIGINAL | 1791.03 | XTO Masterplan | 47.2401 | 0.422238 | 56 | 1791.03 | 0.00601785 | 60 | 0.211119 | 0.00601785 | Identity Data - TA Workset: yes
18203382 | 18203014 | ORIGINAL | 880 | XTO Masterplan | 23.2109 | 0.21088 | 56 | 880 | 0.0029568 | 60 | 0.10544 | 0.0029568 | Identity Data - TA Workset: yes
3065862 | 3065420 | RESULT |  | XTA Terminal A | 36.0954 | 0.324332 | 56 | 1377 | 0.00459815 | 60
18203369 | 18203014 | RESULT |  | XTO Masterplan | 34.749 | 0.312489 | 56 | 1326 | 0.00442663 | 60 | Identity Data - TA Workset: yes
3065870 | 3065420 | RESULT |  | XTA Terminal A | 36.0954 | 0.324332 | 56 | 1377 | 0.00459815 | 60
3065884 | 3065420 | RESULT |  | XTA Terminal A | 36.0954 | 0.324332 | 56 | 1377 | 0.00459815 | 60

# IfcPlate: Curtain Panel:Curtain Panel, Curtain Panel:Curtain Panel:7958512
In: H01 Hovedetasje
Type - PredefinedType: CURTAIN_PANEL; Material: <Unnamed>
Type - Other - Category: Curtain Panels; Family Name: Curtain Panel
Type - Identity Data - Type Name: Curtain Panel; Workset: XTA Terminal A
Type - Analytical Properties - Analytic Construction: <None>; Define Thermal Properties by: Schematic Type
Type - Pset_PlateCommon - IsExternal: no
Constraints - Level: H01 Hovedetasje
Other - Family and Type: Curtain Panel: Curtain Panel; Family: Curtain Panel; Type: Curtain Panel; Type Id: 8557609; Host Id: 5660698
Pset_PlateCommon - IsExternal: yes; Reference: Curtain Panel
Identity Data - TA Workset: yes; E203 TETT BYGG: yes; E204 INNVENDIGE: no
Phasing - Phase Created: Som Bygget
ePset_SimplebimBasicQuantities - Volume, net (Simplebim): 0.222225 m3; Area, largest surface, net (Simplebim): 4.4445 m2; Weight, as steel (Simplebim): 1744.47 kg
Pset_QuantityTakeOff - Reference: Curtain Panel
ePset_LocationTool - Splitting: ORIGINAL
Dimensions - Volume: 0.222225 m3; Area: 4.4445 m2
ePset_Simplebim - Assembly Level: Leaf

# IfcPlate: System Panel:Glazed-generic (42)
In: H01 Hovedetasje
Type - PredefinedType: CURTAIN_PANEL; Material: Glass 01_jb
Type - Other - Category: Curtain Panels; Family Name: System Panel
Type - Constraints - Offset: 8.5 mm
Type - Dimensions - Thickness: 48 mm
Type - Identity Data - Type Name: Glazed-generic; Workset: Family : Curtain Panels : System Panel
Type - Materials and Finishes - Material: Glass 01_jb
Type - Analytical Properties - Analytic Construction: <None>; Define Thermal Properties by: Schematic Type
Type - Pset_PlateCommon - IsExternal: no
Pset_PlateCommon - Reference: Glazed-generic
Phasing - Phase Created: Som Bygget
Pset_QuantityTakeOff - Reference: Glazed-generic
Other - Type: Glazed-generic; Family: System Panel; Type Id: 403254; Family and Type: System Panel: Glazed-generic
ePset_Simplebim - Assembly Level: Leaf
Name (System Panel:Glazed-generic:...) | Area (m2) | Height (mm) | Width (mm) | Volume (m3) | Workset | Area, largest surface, net (Simplebim) (m2) | Weight, as steel (Simplebim) (kg) | Volume, net (Simplebim) (m3) | Splitting | Host Id | TA Workset
3065459 | 2.5704 | 952 | 2700 | 0.123379 | XTA Terminal A | 2.5704 | 968.527 | 0.123379 | ORIGINAL | 3065420
3065461 | 2.54374 | 952 | 2672 | 0.1221 | XTA Terminal A | 2.54374 | 958.483 | 0.1221 | ORIGINAL | 3065420
3065463 | 2.51709 | 952 | 2644 | 0.12082 | XTA Terminal A | 2.51709 | 948.439 | 0.12082 | ORIGINAL | 3065420
3065465 | 2.51709 | 952 | 2644 | 0.12082 | XTA Terminal A | 2.51709 | 948.439 | 0.12082 | ORIGINAL | 3065420
3065467 | 2.55301 | 952 | 2681.73 | 0.122544 | XTA Terminal A | 2.55301 | 961.974 | 0.122544 | ORIGINAL | 3065420
3065680 | 0.419134 | 952 | 440.267 | 0.0201184 | XTA Terminal A | 0.419134 | 157.93 | 0.0201184 | ORIGINAL | 3065420 | yes
3065488 | 4.6953 | 1739 | 2700 | 0.225374 | XTA Terminal A | 4.6953 | 1769.19 | 0.225374 | ORIGINAL | 3065420
3065489 | 4.64661 | 1739 | 2672 | 0.223037 | XTA Terminal A | 4.64661 | 1750.84 | 0.223037 | ORIGINAL | 3065420
3065490 | 4.59792 | 1739 | 2644 | 0.2207 | XTA Terminal A | 4.59792 | 1732.49 | 0.2207 | ORIGINAL | 3065420
3065491 | 4.59792 | 1739 | 2644 | 0.2207 | XTA Terminal A | 4.59792 | 1732.49 | 0.2207 | ORIGINAL | 3065420
3065492 | 4.66353 | 1739 | 2681.73 | 0.22385 | XTA Terminal A | 4.66353 | 1757.22 | 0.22385 | ORIGINAL | 3065420
3065681 | 0.765624 | 1739 | 440.267 | 0.03675 | XTA Terminal A | 0.765624 | 288.487 | 0.03675 | ORIGINAL | 3065420 | yes
18203057 | 0.078225 | 28.9722 | 2700 | 0.0037548 | XTO Masterplan | 0.1296 | 29.4752 | 0.0037548 | ORIGINAL | 18203014 | yes
18203059 | 0.0775219 | 28.9722 | 2675.73 | 0.00372105 | XTO Masterplan | 0.128435 | 29.2103 | 0.00372105 | ORIGINAL | 18203014 | yes
18203061 | 0.0796011 | 28.9722 | 2747.5 | 0.00382085 | XTO Masterplan | 0.13188 | 29.9937 | 0.00382085 | ORIGINAL | 18203014 | yes
18203188 | 0.0777179 | 28.9722 | 2682.5 | 0.00373046 | XTO Masterplan | 0.12876 | 29.2841 | 0.00373046 | ORIGINAL | 18203014 | yes
18203195 | 0.0599725 | 28.9722 | 2070 | 0.00287868 | XTO Masterplan | 0.09936 | 22.5976 | 0.00287868 | ORIGINAL | 18203014 | yes
18203202 | 0.0181976 | 28.9722 | 628.105 | 0.000873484 | XTO Masterplan | 0.030149 | 6.85685 | 0.000873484 | ORIGINAL | 18203014 | yes
18203267 | 2.376 | 880 | 2700 | 0.114048 | XTO Masterplan | 2.376 | 895.277 | 0.114048 | ORIGINAL | 18203014 | yes
18203268 | 2.35465 | 880 | 2675.73 | 0.113023 | XTO Masterplan | 2.35465 | 887.23 | 0.113023 | ORIGINAL | 18203014 | yes
18203269 | 2.4178 | 880 | 2747.5 | 0.116054 | XTO Masterplan | 2.4178 | 911.027 | 0.116054 | ORIGINAL | 18203014 | yes
18203270 | 2.3606 | 880 | 2682.5 | 0.113309 | XTO Masterplan | 2.3606 | 889.474 | 0.113309 | ORIGINAL | 18203014 | yes
18203271 | 1.8216 | 880 | 2070 | 0.0874368 | XTO Masterplan | 1.8216 | 686.379 | 0.0874368 | ORIGINAL | 18203014 | yes
18203272 | 0.503453 | 880 | 572.105 | 0.0241657 | XTO Masterplan | 0.503453 | 189.701 | 0.0241657 | ORIGINAL | 18203014 | yes
18203238 | 4.83578 | 1791.03 | 2700 | 0.232117 | XTO Masterplan | 4.83577 | 1822.12 | 0.232117 | ORIGINAL | 18203014 | yes
18203239 | 4.79231 | 1791.03 | 2675.73 | 0.230031 | XTO Masterplan | 4.79231 | 1805.74 | 0.230031 | ORIGINAL | 18203014 | yes
18203240 | 4.92085 | 1791.03 | 2747.5 | 0.236201 | XTO Masterplan | 4.92085 | 1854.18 | 0.236201 | ORIGINAL | 18203014 | yes
18203241 | 4.80443 | 1791.03 | 2682.5 | 0.230613 | XTO Masterplan | 4.80443 | 1810.31 | 0.230613 | ORIGINAL | 18203014 | yes
18203242 | 3.70743 | 1791.03 | 2070 | 0.177957 | XTO Masterplan | 3.70743 | 1396.96 | 0.177957 | ORIGINAL | 18203014 | yes
18203243 | 1.02466 | 1791.03 | 572.105 | 0.0491835 | XTO Masterplan | 1.02466 | 386.09 | 0.0491835 | ORIGINAL | 18203014 | yes | Identity Data - E203 TETT BYGG: yes
3065516 |  |  |  |  | XTA Terminal A | 3.56749 | 1337.77 | 0.170417 | RESULT | 3065420
3065517 |  |  |  |  | XTA Terminal A | 3.61841 | 1356.86 | 0.172849 | RESULT | 3065420
3065682 |  |  |  |  | XTA Terminal A | 0.594043 | 222.759 | 0.028377 | RESULT | 3065420 | yes
18203189 |  |  |  |  | XTO Masterplan | 3.55762 | 1333.95 | 0.16993 | RESULT | 18203014 | yes
18203196 |  |  |  |  | XTO Masterplan | 2.7453 | 1029.37 | 0.13113 | RESULT | 18203014 | yes
18203203 |  |  |  |  | XTO Masterplan | 0.758744 | 284.497 | 0.0362416 | RESULT | 18203014 | yes
3065513 |  |  |  |  | XTA Terminal A | 3.27197 | 1226.95 | 0.1563 | RESULT | 3065420
3065514 |  |  |  |  | XTA Terminal A | 3.60527 | 1351.94 | 0.172221 | RESULT | 3065420
3065515 |  |  |  |  | XTA Terminal A | 3.56749 | 1337.77 | 0.170417 | RESULT | 3065420
18203084 |  |  |  |  | XTO Masterplan | 3.21179 | 1204.29 | 0.153412 | RESULT | 18203014 | yes
18203085 |  |  |  |  | XTO Masterplan | 3.54864 | 1330.59 | 0.169502 | RESULT | 18203014 | yes
18203086 |  |  |  |  | XTO Masterplan | 3.64382 | 1366.28 | 0.174048 | RESULT | 18203014 | yes

# IfcPlate: System Panel:Værnes 50 (E203) Back Painted (2)
In: H01 Hovedetasje
Type - PredefinedType: CURTAIN_PANEL; Material: Glass - Back painted
Type - Other - Category: Curtain Panels; Family Name: System Panel
Type - Constraints - Offset: 0 mm
Type - Dimensions - Thickness: 50 mm
Type - Identity Data - Type Name: Værnes 50 (E203) Back Painted; Workset: Family : Curtain Panels : System Panel
Type - Materials and Finishes - Material: Glass - Back painted
Type - Analytical Properties - Analytic Construction: <None>; Define Thermal Properties by: Schematic Type
Type - Pset_PlateCommon - IsExternal: no
Pset_PlateCommon - IsExternal: yes; Reference: Værnes 50 (E203) Back Painted
Constraints - Level: H01 Hovedetasje
Other - Family and Type: System Panel: Værnes 50 (E203) Back Painted; Type Id: 9390967; Family: System Panel; Type: Værnes 50 (E203) Back Painted; Host Id: 5660698
ePset_LocationTool - Splitting: ORIGINAL
Identity Data - TA Workset: yes; E203 TETT BYGG: yes; E204 INNVENDIGE: no; Workset: XTA Terminal A
Pset_QuantityTakeOff - Reference: Værnes 50 (E203) Back Painted
Phasing - Phase Created: Som Bygget
ePset_Simplebim - Assembly Level: Leaf
Name (System Panel:Værnes 50 (E203) Back Painted:...) | Weight, as steel (Simplebim) (kg) | Area, largest surface, net (Simplebim) (m2) = Area (m2) | Volume, net (Simplebim) (m3) = Volume (m3)
7958511 | 926.134 | 2.35958 | 0.117979
7958513 | 1378.52 | 3.51214 | 0.175607

# IfcSlab: Floor:NSW Gulv - Betong 120 + 10 mm flis, Floor:NSW Gulv - Betong 120 + 10 mm flis:5401128
In: H01 Hovedetasje
Type - PredefinedType: FLOOR; Material: air 12 mm, _NSW Betong 120 mm, _NSW Isolasjon 200 mm
Type - Other - Category: Floors; Family Name: Floor
Type - Construction - Function: Interior; Default Thickness: 332 mm
Type - Graphics - Coarse Scale Fill Color: 0
Type - Identity Data - Type Name: NSW Gulv - Betong 120 + 10 mm flis; Workset: Floor Types
Type - Materials and Finishes - Structural Material: _NSW Isolasjon
Type - Text - Gulv Code: -
Type - Analytical Properties - Roughness: 1; Absorptance: 0.1
Type - Pset_SlabCommon - IsExternal: no
ePset_SimplebimBasicQuantities - Area, top, net (Simplebim): 118.929 m2; Area, largest surface, net (Simplebim): 118.929 m2; Perimeter (Simplebim): 44051.8 mm; Volume, net (Simplebim): 39.4844 m3; Area, sides, net (Simplebim): 14.6252 m2; Thickness (Simplebim): 332 mm
Constraints - Level: H01 Hovedetasje; Related to Mass: no; Room Bounding: yes
ePset_Simplebim - Assembly Level: Leaf
Pset_QuantityTakeOff - Reference: NSW Gulv - Betong 120 + 10 mm flis; sets with these values: 2
ePset_LocationTool - Splitting: RESULT
Pset_SlabCommon - Reference: NSW Gulv - Betong 120 + 10 mm flis; LoadBearing: no
Phasing - Phase Created: Som Bygget
Other - Type: NSW Gulv - Betong 120 + 10 mm flis; Type Id: 5349859; Family and Type: Floor: NSW Gulv - Betong 120 + 10 mm flis; Family: Floor
Structural - Structural: no
Identity Data - Workset: TA-TC - Struktur; Has Association: no

# IfcSlab: Floor:VÆRNES - GULV 01 - MATT FLIS (3)
In: H01 Hovedetasje
Type - PredefinedType: FLOOR; Material: Værnes_Flis 01 10 mm, Værnes_Mørtel 2 mm
Type - Other - Category: Floors; Family Name: Floor
Type - Construction - Function: Interior; Default Thickness: 12 mm
Type - Graphics - Coarse Scale Fill Color: 0
Type - Identity Data - Type Name: VÆRNES - GULV 01 - MATT FLIS; Workset: Floor Types
Type - Materials and Finishes - Structural Material: Værnes_Flis 01
Type - Text - Gulv Code: FLIS 01
Type - Analytical Properties - Roughness: 1; Absorptance: 0.1
Type - Pset_SlabCommon - IsExternal: no
ePset_Simplebim - Assembly Level: Leaf
Text - Entreprisenummer: E204
Other - Type Id: 5019650; Family and Type: Floor: VÆRNES - GULV 01 - MATT FLIS; Type: VÆRNES - GULV 01 - MATT FLIS; Family: Floor
Identity Data - TA Workset: yes; E204 INNVENDIGE: yes; Has Association: no; Workset: XTA Terminal A
Phasing - Phase Created: Som Bygget
Pset_SlabCommon - Reference: VÆRNES - GULV 01 - MATT FLIS; LoadBearing: no
Structural - Structural: no
Constraints - Level: H01 Hovedetasje; Related to Mass: no; Room Bounding: yes
Pset_ReinforcementBarPitchOfSlab - Reference: VÆRNES - GULV 01 - MATT FLIS; sets with these values: 2
ePset_SimplebimBasicQuantities - Thickness (Simplebim): 12 mm
Name (Floor:VÆRNES - GULV 01 - MATT FLIS:...) | Splitting | Volume, net (Simplebim) (m3) | Area, sides, net (Simplebim) (m2) | Area, largest surface, net (Simplebim) (m2) = Area, top, net (Simplebim) (m2) | Perimeter (Simplebim) (mm)
6203156 | ORIGINAL | 0.14237 | 0.206829 | 11.8642 | 17235.8 | Dimensions - Volume: 0.14237 m3; Area: 11.8642 m2; Thickness: 12 mm; Elevation at Top: 9320 mm; Elevation at Top Core: 9320 mm; Elevation at Bottom: 9308 mm; Elevation at Bottom Core: 9308 mm; Perimeter: 17238.9 mm; Pset_SlabCommon - PitchAngle: 0 deg; Constraints - Height Offset From Level: 0 mm
6203163 | RESULT | 0.754065 | 0.384202 | 62.8388 | 32016.8
6203184 | RESULT | 0.106371 | 0.206138 | 8.86419 | 17178.2

# IfcSlab: Floor:VÆRNES - GULV 02 - POLERT FLIS (12)
In: H01 Hovedetasje
Type - PredefinedType: FLOOR; Material: Værnes_Flis 02 Polert 10 mm, Værnes_Mørtel 2 mm
Type - Other - Category: Floors; Family Name: Floor
Type - Construction - Function: Interior; Default Thickness: 12 mm
Type - Graphics - Coarse Scale Fill Color: 1644825
Type - Identity Data - Type Name: VÆRNES - GULV 02 - POLERT FLIS; Workset: Floor Types
Type - Materials and Finishes - Structural Material: Værnes_Flis 02 Polert
Type - Text - Gulv Code: FLIS 02
Type - Analytical Properties - Roughness: 1; Absorptance: 0.1
Type - Pset_SlabCommon - IsExternal: no
ePset_Simplebim - Assembly Level: Leaf
Pset_QuantityTakeOff - Reference: VÆRNES - GULV 02 - POLERT FLIS; sets with these values: 2
Pset_SlabCommon - LoadBearing: no; Reference: VÆRNES - GULV 02 - POLERT FLIS
Text - Entreprisenummer: E204
ePset_SimplebimBasicQuantities - Thickness (Simplebim): 12 mm
Identity Data - TA Workset: yes; E204 INNVENDIGE: yes; Has Association: no; Workset: XTA Terminal A
Phasing - Phase Created: Som Bygget
Other - Type Id: 6158924; Type: VÆRNES - GULV 02 - POLERT FLIS; Family and Type: Floor: VÆRNES - GULV 02 - POLERT FLIS; Family: Floor
Structural - Structural: no
Constraints - Level: H01 Hovedetasje; Related to Mass: no; Room Bounding: yes
Name (Floor:VÆRNES - GULV 02 - POLERT FLIS:...) | Area, sides, net (Simplebim) (m2) | Volume, net (Simplebim) (m3) | Area, largest surface, net (Simplebim) (m2) = Area, top, net (Simplebim) (m2) | Perimeter (Simplebim) (mm) | Splitting
6203324 | 0.0578017 | 0.00502857 | 0.419047 | 4816.81 | ORIGINAL | Pset_SlabCommon - PitchAngle: 0 deg; Dimensions - Area: 0.41808 m2; Thickness: 12 mm; Elevation at Top: 9320 mm; Elevation at Top Core: 9320 mm; Elevation at Bottom: 9308 mm; Elevation at Bottom Core: 9308 mm; Volume: 0.00501667 m3; Perimeter: 4818.8 mm; Constraints - Height Offset From Level: 0 mm
6203359 | 0.18 | 0.04968 | 4.14 | 15000 | ORIGINAL | Pset_SlabCommon - PitchAngle: 0 deg; Dimensions - Area: 4.14 m2; Thickness: 12 mm; Elevation at Top: 9320 mm; Elevation at Top Core: 9320 mm; Elevation at Bottom: 9308 mm; Elevation at Bottom Core: 9308 mm; Volume: 0.04968 m3; Perimeter: 15000 mm; Constraints - Height Offset From Level: 0 mm
6203450 | 0.0658552 | 0.0211279 | 1.76065 | 5487.93 | ORIGINAL | Pset_SlabCommon - PitchAngle: 0 deg; Dimensions - Area: 1.76066 m2; Thickness: 12 mm; Elevation at Top: 9320 mm; Elevation at Top Core: 9320 mm; Elevation at Bottom: 9308 mm; Elevation at Bottom Core: 9308 mm; Volume: 0.0211279 m3; Perimeter: 5486.83 mm; Constraints - Height Offset From Level: 0 mm
12580848 | 0.174417 | 0.0303605 | 2.53004 | 14534.7 | ORIGINAL | Pset_SlabCommon - PitchAngle: 0 deg; Dimensions - Area: 2.53004 m2; Thickness: 12 mm; Elevation at Top: 9320 mm; Elevation at Top Core: 9320 mm; Elevation at Bottom: 9308 mm; Elevation at Bottom Core: 9308 mm; Volume: 0.0303605 m3; Perimeter: 14533.3 mm; Constraints - Height Offset From Level: 0 mm; Identity Data - E203 TETT BYGG: no
12580871 | 0.0333805 | 0.00450569 | 0.375472 | 2781.71 | ORIGINAL | Pset_SlabCommon - PitchAngle: 0 deg; Dimensions - Area: 0.375474 m2; Thickness: 12 mm; Elevation at Top: 9320 mm; Elevation at Top Core: 9320 mm; Elevation at Bottom: 9308 mm; Elevation at Bottom Core: 9308 mm; Volume: 0.00450569 m3; Perimeter: 2781.35 mm; Constraints - Height Offset From Level: 0 mm; Identity Data - E203 TETT BYGG: no
12580880 | 0.0350088 | 0.00340508 | 0.283759 | 2917.4 | ORIGINAL | Pset_SlabCommon - PitchAngle: 0 deg; Dimensions - Area: 0.283757 m2; Thickness: 12 mm; Elevation at Top: 9320 mm; Elevation at Top Core: 9320 mm; Elevation at Bottom: 9308 mm; Elevation at Bottom Core: 9308 mm; Volume: 0.00340508 m3; Perimeter: 2917.74 mm; Constraints - Height Offset From Level: 0 mm; Identity Data - E203 TETT BYGG: no
6203331 | 0.247383 | 0.128061 | 10.6717 | 20615.2 | RESULT
6203352 | 0.232973 | 0.0655709 | 5.46424 | 19414.4 | RESULT
6632064 | 0.226762 | 0.0586781 | 4.88982 | 18896.9 | RESULT | Identity Data - E203 TETT BYGG: no
6203345 | 0.0325541 | 0.00290173 | 0.241811 | 2712.84 | RESULT
6203457 | 0.0556635 | 0.01238 | 1.03167 | 4638.62 | RESULT
12580840 | 0.0232016 | 0.00264005 | 0.220003 | 1933.47 | RESULT | Identity Data - E203 TETT BYGG: no

# IfcSlab: Floor:VÆRNES - GULV 05 - LINOLEUM ANTISTATISK, Floor:VÆRNES - GULV 05 - LINOLEUM ANTISTATISK:11187413
In: H01 Hovedetasje
Type - PredefinedType: FLOOR; Material: Værnes_Linoleum antistatisk 3 mm, Værnes_Kryssfiner 9 mm
Type - Other - Category: Floors; Family Name: Floor
Type - Construction - Function: Interior; Default Thickness: 12 mm
Type - Graphics - Coarse Scale Fill Color: 0
Type - Identity Data - Type Name: VÆRNES - GULV 05 - LINOLEUM ANTISTATISK; Workset: Floor Types
Type - Materials and Finishes - Structural Material: Værnes_Kryssfiner
Type - Text - Gulv Code: LIAS 02
Type - Analytical Properties - Roughness: 1; Absorptance: 0.1
Type - Pset_SlabCommon - IsExternal: no
ePset_Simplebim - Assembly Level: Leaf
Constraints - Level: H01 Hovedetasje; Related to Mass: no; Room Bounding: yes; Height Offset From Level: 2 mm
Pset_SlabCommon - LoadBearing: no; PitchAngle: 0 deg; Reference: VÆRNES - GULV 05 - LINOLEUM ANTISTATISK
Dimensions - Area: 1.64806 m2; Perimeter: 5247.52 mm; Thickness: 12 mm; Elevation at Top: 9322 mm; Elevation at Top Core: 9322 mm; Elevation at Bottom: 9310 mm; Elevation at Bottom Core: 9310 mm; Volume: 0.0197767 m3
Other - Type Id: 6578929; Family and Type: Floor: VÆRNES - GULV 05 - LINOLEUM ANTISTATISK; Family: Floor; Type: VÆRNES - GULV 05 - LINOLEUM ANTISTATISK
Identity Data - TA Workset: yes; E204 INNVENDIGE: yes; Has Association: no; Workset: XTA Terminal A
Phasing - Phase Created: Som Bygget
ePset_SimplebimBasicQuantities - Perimeter (Simplebim): 5247.24 mm; Area, largest surface, net (Simplebim): 1.64806 m2; Area, top, net (Simplebim): 1.64806 m2; Thickness (Simplebim): 12 mm; Volume, net (Simplebim): 0.0197767 m3; Area, sides, net (Simplebim): 0.0629669 m2
ePset_LocationTool - Splitting: ORIGINAL
Structural - Structural: no
Pset_QuantityTakeOff - Reference: VÆRNES - GULV 05 - LINOLEUM ANTISTATISK; sets with these values: 2

# IfcSlab: Floor:Værnes Betong 350mm, Floor:Værnes Betong 350mm:6722007
In: H01 Hovedetasje
Type - PredefinedType: FLOOR; Material: Værnes_Flis Existing_Pink 12 mm, Værnes_Betong 350 mm
Type - Other - Category: Floors; Family Name: Floor
Type - Construction - Function: Interior; Default Thickness: 362 mm
Type - Graphics - Coarse Scale Fill Color: 0
Type - Identity Data - Type Name: Værnes Betong 350mm; Workset: Floor Types
Type - Materials and Finishes - Structural Material: Værnes_Betong
Type - Text - Gulv Code: -
Type - Analytical Properties - Roughness: 1; Absorptance: 0.1
Type - Pset_SlabCommon - IsExternal: no
Constraints - Level: H01 Hovedetasje; Related to Mass: no; Room Bounding: yes
ePset_Simplebim - Assembly Level: Leaf
Identity Data - TA Workset: yes; Has Association: no; Workset: XTA Terminal A
Phasing - Phase Created: Som Bygget
Other - Family and Type: Floor: Værnes Betong 350mm; Type: Værnes Betong 350mm; Type Id: 212970; Family: Floor
Structural - Structural: no
ePset_LocationTool - Splitting: RESULT
Visibility - N/R BIM do not use: yes
ePset_SimplebimBasicQuantities - Area, largest surface, net (Simplebim): 117.592 m2; Area, top, net (Simplebim): 117.592 m2; Volume, net (Simplebim): 42.5681 m3; Area, sides, net (Simplebim): 16.158 m2; Perimeter (Simplebim): 44635.3 mm; Thickness (Simplebim): 362 mm
Pset_SlabCommon - LoadBearing: no; Reference: Værnes Betong 350mm
Pset_QuantityTakeOff - Reference: Værnes Betong 350mm; sets with these values: 2

# IfcSlab: Floor:Værnes_Betong Floor 250, Floor:Værnes_Betong Floor 250:3821175
In: XX - C +8,70
Type - PredefinedType: FLOOR; Material: Værnes_Betong 250 mm
Type - Other - Category: Floors; Family Name: Floor
Type - Construction - Function: Interior; Default Thickness: 250 mm
Type - Graphics - Coarse Scale Fill Color: 0
Type - Identity Data - Type Name: Værnes_Betong Floor 250; Workset: Floor Types
Type - Materials and Finishes - Structural Material: Værnes_Betong
Type - Text - Gulv Code: -
Type - Analytical Properties - Roughness: 1; Absorptance: 0.1
Type - Pset_SlabCommon - IsExternal: no
Constraints - Level: XX - C +8,70; Related to Mass: no; Room Bounding: yes
ePset_Simplebim - Assembly Level: Leaf
ePset_SimplebimBasicQuantities - Perimeter (Simplebim): 36189.1 mm; Area, top, net (Simplebim): 20.7028 m2; Area, largest surface, net (Simplebim): 20.7028 m2; Volume, net (Simplebim): 5.17569 m3; Thickness (Simplebim): 250 mm; Area, sides, net (Simplebim): 9.04727 m2
ePset_LocationTool - Splitting: RESULT
Identity Data - TA Workset: yes; E204 INNVENDIGE: no; E203 TETT BYGG: no; Has Association: no; Workset: XTA Terminal A
Pset_ReinforcementBarPitchOfSlab - Reference: Værnes_Betong Floor 250; sets with these values: 2
Phasing - Phase Created: Som Bygget
Pset_SlabCommon - Reference: Værnes_Betong Floor 250; LoadBearing: no
Other - Type: Værnes_Betong Floor 250; Family and Type: Floor: Værnes_Betong Floor 250; Type Id: 4251949; Family: Floor
Structural - Structural: no
Visibility - N/R BIM do not use: yes

# IfcSlab: Floor:Værnes_Betong Floor 250-External (2)
Pset_SlabCommon - IsExternal: yes; LoadBearing: no; PitchAngle: 0 deg; Reference: Værnes_Betong Floor 250-External
Dimensions - Thickness: 250 mm
ePset_Simplebim - Assembly Level: Topmost
Phasing - Phase Created: Som Bygget
Constraints - Related to Mass: no; Room Bounding: yes
Identity Data - TA Workset: yes; E204 INNVENDIGE: no; E203 TETT BYGG: yes; Has Association: no
Other - Type Id: 5596932; Category: Floors; Type: Værnes_Betong Floor 250-External; Family and Type: Floor: Værnes_Betong Floor 250-External; Family: Floor
Pset_QuantityTakeOff - Reference: Værnes_Betong Floor 250-External; sets with these values: 2
Structural - Structural: no
Slab Shape Edit - Curved Edge Condition: 0
ePset_SimplebimBasicQuantities - Width: 38201.1 mm; Height: 250 mm; Length: 68658 mm
Name (Floor:Værnes_Betong Floor 250-External:...) | In | Perimeter (mm) | Volume (m3) = Volume, net (Simplebim) (m3) | Area (m2) | Level | Height Offset From Level (mm) | Workset
4396355 | H01 Hovedetasje | 220489 | 74.9965 | 299.986 | H01 Hovedetasje | -200 | TA-TC - Struktur
9229341 | XX - C +10,75 TA E1 | 212481 | 93.8155 | 375.262 | XX - C +10,75 TA E1 | -1600 | XTA Terminal A

# IfcSlab: Floor:Værnes_Betong Floor 250-External (2)
Type - Other - Category: Floors; Family Name: Floor
Type - Construction - Function: Exterior; Default Thickness: 250 mm
Type - Graphics - Coarse Scale Fill Color: 0
Type - Identity Data - Type Name: Værnes_Betong Floor 250-External; Workset: Floor Types
Type - Materials and Finishes - Structural Material: Værnes_Betong
Type - Text - Gulv Code: -
Type - Analytical Properties - Roughness: 1; Absorptance: 0.1
Type - Pset_SlabCommon - IsExternal: yes
ePset_Simplebim - Assembly Level: Leaf
ePset_SimplebimBasicQuantities - Thickness (Simplebim): 250 mm
Pset_QuantityTakeOff - Reference: Værnes_Betong Floor 250-External; sets with these values: 2
Pset_SlabCommon - LoadBearing: no; Reference: Værnes_Betong Floor 250-External
ePset_LocationTool - Splitting: RESULT
Name (Floor:Værnes_Betong Floor 250-External:...) | In | Perimeter (Simplebim) (mm) | Volume, net (Simplebim) (m3) | Area, sides, net (Simplebim) (m2) | Area, largest surface, net (Simplebim) (m2) = Area, top, net (Simplebim) (m2)
4396355 | H01 Hovedetasje | 11771.6 | 2.12452 | 2.9429 | 8.49806
9229341 | XX - C +10,75 TA E1 | 11601.5 | 2.07052 | 2.90038 | 8.28206

# IfcWall: Basic Wall:232_Værnes Yttervegg 08_200mm Ekspedisjons vegg, Basic Wall:232_Værnes Yttervegg 08_200mm Ekspedisjons vegg:18203367
In: XX - C +10,75 TA E1
Type - Material: Værnes_Metalpanel 25 mm, Værnes_Luftspalte 20 mm, Værnes_Vindsperre 22 mm, Værnes_Isolasjon-Mineralull 50 mm, Værnes_Stender isolert 200 mm
Type - Other - Category: Walls; Family Name: Basic Wall
Type - Construction - Function: Exterior; Width: 317 mm; Wrapping at Inserts: Both
Type - Graphics - Coarse Scale Fill Color: 0
Type - Identity Data - Type Name: 232_Værnes Yttervegg 08_200mm Ekspedisjons vegg; Workset: Wall Types
Type - Materials and Finishes - Structural Material: Værnes_Stender isolert
Type - Analytical Properties - Absorptance: 0.1; Roughness: 1
Type - Pset_WallCommon - IsExternal: yes
Type - Text - Vegg Kode: YV08
Other - Family: Basic Wall; Type Id: 5787319; Type: 232_Værnes Yttervegg 08_200mm Ekspedisjons vegg; Family and Type: Basic Wall: 232_Værnes Yttervegg 08_200mm Ekspedisjons vegg
ePset_SimplebimBasicQuantities - Area, side, gross, average (Simplebim): 1.33041 m2; Area, side, net, smaller (Simplebim): 1.33041 m2; Area, side, net, average (Simplebim): 1.33041 m2; Area, side, gross, smaller (Simplebim): 1.33041 m2; Area, side, net, larger (Simplebim): 1.33041 m2; Area, side, gross, larger (Simplebim): 1.33041 m2; Area, largest surface, net (Simplebim): 4.08462 m2; Area, side, gross, AABB (Simplebim): 5.72161 m2; Thickness (Simplebim): 973 mm; Length (Simplebim): 1411 mm; Height (Simplebim): 4055 mm; Volume, net (Simplebim): 1.29482 m3
ePset_Simplebim - Assembly Level: Leaf
Pset_WallCommon - Reference: 232_Værnes Yttervegg 08_200mm Ekspedisjons vegg
Phasing - Phase Created: Som Bygget
Pset_QuantityTakeOff - Reference: 232_Værnes Yttervegg 08_200mm Ekspedisjons vegg; sets with these values: 2
Identity Data - TA Workset: yes; E203 TETT BYGG: yes; Workset: XTO Masterplan
Constraints - Reference Level: XX - C +10,75 TA E1; Location Line: Finish Face: Exterior; Related to Mass: no; Room Bounding: yes
ePset_LocationTool - Splitting: RESULT

# IfcWall: Basic Wall:242_Værnes Innervegg 15_100mm, Basic Wall:242_Værnes Innervegg 15_100mm:18203387
In: H01 Hovedetasje
Type - PredefinedType: STANDARD; Material: Værnes_Malt 2 mm, Værnes_Gipsplate waterproof 13 mm, Værnes_Stålstender, uisolert 100 mm
Type - Other - Category: Walls; Family Name: Basic Wall
Type - Construction - Function: Interior; Width: 115 mm; Wrapping at Inserts: Do not wrap
Type - Graphics - Coarse Scale Fill Color: 12632256; Coarse Scale Fill Pattern: <Solid fill>
Type - Identity Data - Type Name: 242_Værnes Innervegg 15_100mm; Workset: Wall Types
Type - Materials and Finishes - Structural Material: Værnes_Stålstender, uisolert
Type - Analytical Properties - Absorptance: 0.1; Roughness: 1
Type - Pset_WallCommon - IsExternal: no; FireRating: E160 (A60) WHEN USED IN CONJUNCTION WITH 28
Type - Text - Core Kode: 100G M0; Vegg Kode: IV15
Type - Pset_ConcreteElementGeneral - FireRating: E160 (A60) WHEN USED IN CONJUNCTION WITH 28
ePset_Simplebim - Assembly Level: Leaf
Pset_WallCommon - Reference: 242_Værnes Innervegg 15_100mm; ExtendToStructure: no; LoadBearing: no
Identity Data - TA Workset: yes; Workset: XTO Masterplan
ePset_LocationTool - Splitting: RESULT
Cross-Section Definition - Cross-Section: Vertical
Phasing - Phase Created: Som Bygget
Structural - Structural Usage: Non-bearing; Structural: no
Constraints - Top Constraint: Up to level: XX - C +15,37 TA E2; Base Constraint: H01 Hovedetasje; Location Line: Wall Centerline; Base is Attached: no; Related to Mass: no; Room Bounding: yes; Top is Attached: no
Other - Type: 242_Værnes Innervegg 15_100mm; Family: Basic Wall; Family and Type: Basic Wall: 242_Værnes Innervegg 15_100mm; Type Id: 3570145
ePset_SimplebimBasicQuantities - Area, side, net, larger (Simplebim): 2.77279 m2; Area, side, gross, smaller (Simplebim): 2.77279 m2; Area, side, net, average (Simplebim): 2.77279 m2; Area, side, net, smaller (Simplebim): 2.77279 m2; Area, side, gross, average (Simplebim): 2.77279 m2; Area, largest surface, net (Simplebim): 2.77279 m2; Area, side, gross, larger (Simplebim): 2.77279 m2; Area, side, gross, AABB (Simplebim): 7.104 m2; Thickness (Simplebim): 114 mm; Length (Simplebim): 1776 mm; Height (Simplebim): 4000 mm; Volume, net (Simplebim): 0.318871 m3
Pset_QuantityTakeOff - Reference: 242_Værnes Innervegg 15_100mm; sets with these values: 2

# IfcWall: Basic Wall:242_Værnes Innervegg 16_100mm, Basic Wall:242_Værnes Innervegg 16_100mm:5895479
In: H01 Hovedetasje
Type - PredefinedType: STANDARD; Material: Værnes_Malt 2 mm, Værnes_Gipsplate 13 mm, Værnes_Gipsplate 13 mm, Værnes_Stålstender 100 mm
Type - Other - Category: Walls; Family Name: Basic Wall
Type - Construction - Function: Interior; Width: 128 mm; Wrapping at Inserts: Both
Type - Graphics - Coarse Scale Fill Color: 12632256; Coarse Scale Fill Pattern: <Solid fill>
Type - Identity Data - Type Name: 242_Værnes Innervegg 16_100mm; Workset: Wall Types
Type - Materials and Finishes - Structural Material: Værnes_Stålstender
Type - Analytical Properties - Absorptance: 0.1; Roughness: 1
Type - Pset_WallCommon - IsExternal: no; FireRating: E160 (A60) WHEN USED IN TWO LAYERS
Type - Text - Core Kode: 100GG M0; Vegg Kode: IV16
Type - Pset_ConcreteElementGeneral - FireRating: E160 (A60) WHEN USED IN TWO LAYERS
Pset_WallCommon - Reference: 242_Værnes Innervegg 16_100mm; ExtendToStructure: no; LoadBearing: no
ePset_Simplebim - Assembly Level: Leaf
Cross-Section Definition - Cross-Section: Vertical
Phasing - Phase Created: Som Bygget
ePset_SimplebimBasicQuantities - Volume, net (Simplebim): 0.533376 m3; Thickness (Simplebim): 128 mm; Length (Simplebim): 1042 mm; Height (Simplebim): 4000 mm; Area, side, net, smaller (Simplebim): 4.167 m2; Area, side, net, average (Simplebim): 4.167 m2; Area, side, gross, smaller (Simplebim): 4.167 m2; Area, side, net, larger (Simplebim): 4.167 m2; Area, largest surface, net (Simplebim): 4.167 m2; Area, side, gross, average (Simplebim): 4.167 m2; Area, side, gross, larger (Simplebim): 4.167 m2; Area, side, gross, AABB (Simplebim): 4.168 m2
Structural - Structural Usage: Non-bearing; Structural: no
Constraints - Top Constraint: Up to level: XX - C +15,37 TA E2; Base Constraint: H01 Hovedetasje; Base is Attached: no; Related to Mass: no; Room Bounding: yes; Top is Attached: no; Location Line: Core Centerline
Identity Data - TA Workset: yes; E204 INNVENDIGE: yes; E203 TETT BYGG: no; Workset: XTA Terminal A
Pset_QuantityTakeOff - Reference: 242_Værnes Innervegg 16_100mm; sets with these values: 2
Other - Type: 242_Værnes Innervegg 16_100mm; Family: Basic Wall; Family and Type: Basic Wall: 242_Værnes Innervegg 16_100mm; Type Id: 5876982; Kontor Blokk innervegg: no; Shaft Paint to exclude: yes
ePset_LocationTool - Splitting: RESULT

# IfcWall: Basic Wall:242_Værnes Innervegg 17_100mm (2)
In: H01 Hovedetasje
Type - PredefinedType: STANDARD; Material: Værnes_Malt 2 mm, Værnes_Gipsplate 13 mm, Værnes_Stålstender, isolert 100 mm, Værnes_Gipsplate waterproof 13 mm, Værnes_Malt 2 mm
Type - Other - Category: Walls; Family Name: Basic Wall
Type - Construction - Function: Interior; Width: 130 mm; Wrapping at Inserts: Do not wrap
Type - Graphics - Coarse Scale Fill Color: 12632256; Coarse Scale Fill Pattern: <Solid fill>
Type - Identity Data - Type Name: 242_Værnes Innervegg 17_100mm; Workset: Wall Types; Akustikk: 40 DB
Type - Materials and Finishes - Structural Material: Værnes_Stålstender, isolert
Type - Analytical Properties - Absorptance: 0.1; Roughness: 1
Type - Pset_WallCommon - IsExternal: no
Type - Text - Core Kode: 100G-G M50; Vegg Kode: IV17
ePset_Simplebim - Assembly Level: Leaf
ePset_SimplebimBasicQuantities - Thickness (Simplebim): 130 mm
Cross-Section Definition - Cross-Section: Vertical
Phasing - Phase Created: Som Bygget
ePset_LocationTool - Splitting: RESULT
Structural - Structural Usage: Non-bearing; Structural: no
Other - Type: 242_Værnes Innervegg 17_100mm; Family: Basic Wall; Family and Type: Basic Wall: 242_Værnes Innervegg 17_100mm; Type Id: 7247508
Constraints - Top Constraint: Up to level: M01 Hovedetasje; Base Constraint: H01 Hovedetasje; Base is Attached: no; Related to Mass: no; Room Bounding: yes; Top is Attached: no; Location Line: Finish Face: Interior
Pset_ReinforcementBarPitchOfWall - Reference: 242_Værnes Innervegg 17_100mm; sets with these values: 2
Identity Data - TA Workset: yes; E204 INNVENDIGE: yes; Workset: XTA Terminal A
Pset_WallCommon - Reference: 242_Værnes Innervegg 17_100mm; ExtendToStructure: no; LoadBearing: no
Name (Basic Wall:242_Værnes Innervegg 17_100mm:...) | Area, side, gross, larger (Simplebim) (m2) = Area, largest surface, net (Simplebim) (m2) = Area, side, net, larger (Simplebim) (m2) | Area, side, gross, average (Simplebim) (m2) = Area, side, net, average (Simplebim) (m2) | Area, side, gross, smaller (Simplebim) (m2) = Area, side, net, smaller (Simplebim) (m2) | Volume, net (Simplebim) (m3) | Length (Simplebim) (mm) | Height (Simplebim) (mm) | Area, side, gross, AABB (Simplebim) (m2)
13148436 | 0.317255 | 0.317255 | 0.317255 | 0.0412432 | 486 | 652 | 0.316872
13148431 | 5.9439 | 5.94386 | 5.94381 | 0.772701 | 7900 | 752 | 5.9408

# IfcWall: Basic Wall:242_Værnes Innervegg 77_150mm (2)
Type - Material: Værnes_Flis 05 10 mm, Værnes_Gipsplate 13 mm, Værnes_Gipsplate 13 mm, Værnes_Stålstender 150 mm
Type - Other - Category: Walls; Family Name: Basic Wall
Type - Construction - Function: Interior; Width: 186 mm; Wrapping at Inserts: Do not wrap
Type - Graphics - Coarse Scale Fill Color: 0
Type - Identity Data - Type Name: 242_Værnes Innervegg 77_150mm; Workset: Wall Types
Type - Materials and Finishes - Structural Material: Værnes_Stålstender
Type - Analytical Properties - Absorptance: 0.1; Roughness: 1
Type - Pset_WallCommon - IsExternal: no
Type - Text - Core Kode: 150GG M0; Vegg Kode: IV77
ePset_Simplebim - Assembly Level: Leaf
Phasing - Phase Created: Som Bygget
ePset_LocationTool - Splitting: RESULT
Pset_QuantityTakeOff - Reference: 242_Værnes Innervegg 77_150mm; sets with these values: 2
Other - Family: Basic Wall; Family and Type: Basic Wall: 242_Værnes Innervegg 77_150mm; Type Id: 6762594; Type: 242_Værnes Innervegg 77_150mm
Identity Data - TA Workset: yes; E204 INNVENDIGE: yes
ePset_SimplebimBasicQuantities - Length (Simplebim): 1292 mm
Constraints - Room Bounding: yes
Pset_WallCommon - Reference: 242_Værnes Innervegg 77_150mm
Name (Basic Wall:242_Værnes Innervegg 77_150mm:...) | In | Workset | Area, largest surface, net (Simplebim) (m2) | Volume, net (Simplebim) (m3) | Area, side, gross, larger (Simplebim) (m2) = Area, side, net, average (Simplebim) (m2) = Area, side, net, smaller (Simplebim) (m2) = Area, side, net, larger (Simplebim) (m2) = Area, side, gross, smaller (Simplebim) (m2) = Area, side, gross, average (Simplebim) (m2) | Thickness (Simplebim) (mm) | Height (Simplebim) (mm) | Area, side, gross, AABB (Simplebim) (m2) | Reference Level | Location Line | Related to Mass
18203384 | XX - C +10,75 TA E1 | XTO Masterplan | 3.48443 | 0.648104 | 0.771569 | 840 | 4000 | 5.168 | XX - C +10,75 TA E1 | Wall Centerline | no
6060044 | XX - C +15,37 TA E2 | XTA Terminal A | 5.05236 | 0.939739 | 0.771701 | 1218 | 4001 | 5.16929 | XX - C +15,37 TA E2 | Core Centerline | yes | Identity Data - E203 TETT BYGG: no; Other - Kontor Blokk innervegg: no; Shaft Paint to exclude: yes

# IfcWall: Basic Wall:242_Værnes Innervegg 77_150mm (3)
In: H01 Hovedetasje
Type - PredefinedType: STANDARD; Material: Værnes_Flis 05 10 mm, Værnes_Gipsplate 13 mm, Værnes_Gipsplate 13 mm, Værnes_Stålstender 150 mm
Type - Other - Category: Walls; Family Name: Basic Wall
Type - Construction - Function: Interior; Width: 186 mm; Wrapping at Inserts: Do not wrap
Type - Graphics - Coarse Scale Fill Color: 0
Type - Identity Data - Type Name: 242_Værnes Innervegg 77_150mm; Workset: Wall Types
Type - Materials and Finishes - Structural Material: Værnes_Stålstender
Type - Analytical Properties - Absorptance: 0.1; Roughness: 1
Type - Pset_WallCommon - IsExternal: no
Type - Text - Core Kode: 150GG M0; Vegg Kode: IV77
ePset_Simplebim - Assembly Level: Leaf
ePset_SimplebimBasicQuantities - Thickness (Simplebim): 186 mm; Height (Simplebim): 4000 mm
Cross-Section Definition - Cross-Section: Vertical
Phasing - Phase Created: Som Bygget
Structural - Structural Usage: Non-bearing; Structural: no
Identity Data - TA Workset: yes; E204 INNVENDIGE: yes; Workset: XTA Terminal A
Pset_QuantityTakeOff - Reference: 242_Værnes Innervegg 77_150mm; sets with these values: 2
Other - Family: Basic Wall; Family and Type: Basic Wall: 242_Værnes Innervegg 77_150mm; Type Id: 6762594; Type: 242_Værnes Innervegg 77_150mm
ePset_LocationTool - Splitting: RESULT
Constraints - Base Constraint: H01 Hovedetasje; Base is Attached: no; Related to Mass: no; Room Bounding: yes; Top is Attached: no; Location Line: Core Centerline
Pset_WallCommon - ExtendToStructure: no; LoadBearing: no; Reference: 242_Værnes Innervegg 77_150mm
Name (Basic Wall:242_Værnes Innervegg 77_150mm:...) | Area, side, gross, larger (Simplebim) (m2) = Area, side, gross, average (Simplebim) (m2) = Area, side, gross, smaller (Simplebim) (m2) | Area, largest surface, net (Simplebim) (m2) = Area, side, net, average (Simplebim) (m2) = Area, side, net, smaller (Simplebim) (m2) = Area, side, net, larger (Simplebim) (m2) | Length (Simplebim) (mm) | Area, side, gross, AABB (Simplebim) (m2) | Volume, net (Simplebim) (m3) | E203 TETT BYGG = Kontor Blokk innervegg | Shaft Paint to exclude | Top Constraint
5895648 | 7.13873 | 7.13873 | 1785 | 7.14 | 1.3278 | no | yes | Up to level: M01 Hovedetasje
11590759 | 5.62752 | 4.11552 | 1943 | 7.772 | 0.765486 |  |  | Up to level: M01 Hovedetasje
5895036 | 3.551 | 3.551 | 978 | 3.912 | 0.660485 | no | yes | Up to level: XX - C +15,37 (H02)

# IfcWall: Basic Wall:NSW Utvendig - 250mm (2)
In: U01 Hovedetasje
Type - PredefinedType: STANDARD; Material: _NSW Isolasjon 150 mm, _NSW Betong 250 mm
Type - Other - Category: Walls; Family Name: Basic Wall
Type - Construction - Function: Exterior; Width: 400 mm; Wrapping at Inserts: Do not wrap
Type - Graphics - Coarse Scale Fill Color: 0
Type - Identity Data - Type Name: NSW Utvendig - 250mm; Workset: Wall Types
Type - Materials and Finishes - Structural Material: _NSW Betong
Type - Analytical Properties - Absorptance: 0.1; Roughness: 1
Type - Pset_WallCommon - IsExternal: yes
ePset_Simplebim - Assembly Level: Leaf
ePset_SimplebimBasicQuantities - Thickness (Simplebim): 400 mm; Height (Simplebim): 870 mm
Cross-Section Definition - Cross-Section: Vertical
Phasing - Phase Created: Som Bygget
Pset_ReinforcementBarPitchOfWall - Reference: NSW Utvendig - 250mm; sets with these values: 2
Structural - Structural Usage: Non-bearing; Structural: no
Identity Data - Workset: TA-TC - Struktur
Constraints - Base is Attached: no; Related to Mass: no; Room Bounding: yes; Top is Attached: no; Base Constraint: U01 Hovedetasje
ePset_LocationTool - Splitting: RESULT
Other - Family: Basic Wall; Family and Type: Basic Wall: NSW Utvendig - 250mm; Type: NSW Utvendig - 250mm; Kontor Blokk innervegg: no; Type Id: 135592
Pset_WallCommon - Reference: NSW Utvendig - 250mm; ExtendToStructure: no; LoadBearing: no
Name (Basic Wall:NSW Utvendig - 250mm:...) | Area, side, gross, AABB (Simplebim) (m2) | Volume, net (Simplebim) (m3) | Area, side, net, larger (Simplebim) (m2) = Area, side, gross, smaller (Simplebim) (m2) = Area, side, net, average (Simplebim) (m2) = Area, side, net, smaller (Simplebim) (m2) = Area, side, gross, average (Simplebim) (m2) = Area, largest surface, net (Simplebim) (m2) = Area, side, gross, larger (Simplebim) (m2) | Length (Simplebim) (mm) | Top Constraint | Location Line
2468804 | 2.88492 | 1.15395 | 2.88487 | 3316 | Up to level: U01 Hovedetasje | Core Centerline | Text - Code: TA U1
5867828 | 0.82476 | 0.30447 | 0.761176 | 948 | Up to level: H01 Hovedetasje | Wall Centerline

# IfcWall: Basic Wall:V_Existing 200mm Betong (3)
In: H01 Hovedetasje
Type - PredefinedType: STANDARD; Material: Existing - Bridget key 200 mm
Type - Other - Category: Walls; Family Name: Basic Wall
Type - Construction - Function: Interior; Width: 200 mm; Wrapping at Inserts: Do not wrap
Type - Graphics - Coarse Scale Fill Color: 0
Type - Identity Data - Type Name: V_Existing 200mm Betong; Workset: Wall Types
Type - Materials and Finishes - Structural Material: Existing - Bridget key
Type - Analytical Properties - Absorptance: 0.1; Roughness: 1
Type - Pset_WallCommon - IsExternal: no
Identity Data - Has Association: yes
ePset_Simplebim - Assembly Level: Leaf
Pset_WallCommon - ExtendToStructure: no; LoadBearing: yes; Reference: V_Existing 200mm Betong
Other - Family: Basic Wall; Family and Type: Basic Wall: V_Existing 200mm Betong; Type Id: 4517245; Kontor Blokk innervegg: no; Type: V_Existing 200mm Betong
Constraints - Base Constraint: H01 Hovedetasje; Base is Attached: no; Related to Mass: no; Room Bounding: yes; Top is Attached: no; Top Constraint: Up to level: H01 Hovedetasje; Location Line: Core Face: Exterior
Cross-Section Definition - Cross-Section: Vertical
Phasing - Phase Created: Som Bygget
Structural - Structural: yes; Structural Usage: Bearing; Rebar Cover - Exterior Face: Rebar Cover 1 <25 mm>; Rebar Cover - Interior Face: Rebar Cover 1 <25 mm>; Rebar Cover - Other Faces: Rebar Cover 1 <25 mm>
ePset_SimplebimBasicQuantities - Thickness (Simplebim): 200 mm
ePset_LocationTool - Splitting: RESULT
Pset_ReinforcementBarPitchOfWall - Reference: V_Existing 200mm Betong; sets with these values: 2
Name (Basic Wall:V_Existing 200mm Betong:...) | Workset | Area, side, gross, average (Simplebim) (m2) = Area, largest surface, net (Simplebim) (m2) = Area, side, net, larger (Simplebim) (m2) = Area, side, gross, smaller (Simplebim) (m2) = Area, side, net, average (Simplebim) (m2) = Area, side, net, smaller (Simplebim) (m2) = Area, side, gross, larger (Simplebim) (m2) | Volume, net (Simplebim) (m3) | Area, side, gross, AABB (Simplebim) (m2) | Height (Simplebim) (mm) | Length (Simplebim) (mm) | TA Workset
237007 | TA-TC - Struktur | 3.17784 | 0.635569 | 3.17768 | 668 | 4757
236989 | XTA Terminal A | 2.24576 | 0.449152 | 2.24576 | 638 | 3520 | yes
237721 | XTA Terminal A | 10.1062 | 2.02125 | 10.1062 | 750 | 13475 | yes

# IfcWallStandardCase: Basic Wall:242_Værnes Innervegg 17_100mm (4)
In: H01 Hovedetasje
Type - PredefinedType: STANDARD; Material: Værnes_Malt 2 mm, Værnes_Gipsplate 13 mm, Værnes_Stålstender, isolert 100 mm, Værnes_Gipsplate waterproof 13 mm, Værnes_Malt 2 mm
Type - Other - Category: Walls; Family Name: Basic Wall
Type - Construction - Function: Interior; Width: 130 mm; Wrapping at Inserts: Do not wrap
Type - Graphics - Coarse Scale Fill Color: 12632256; Coarse Scale Fill Pattern: <Solid fill>
Type - Identity Data - Type Name: 242_Værnes Innervegg 17_100mm; Workset: Wall Types; Akustikk: 40 DB
Type - Materials and Finishes - Structural Material: Værnes_Stålstender, isolert
Type - Analytical Properties - Absorptance: 0.1; Roughness: 1
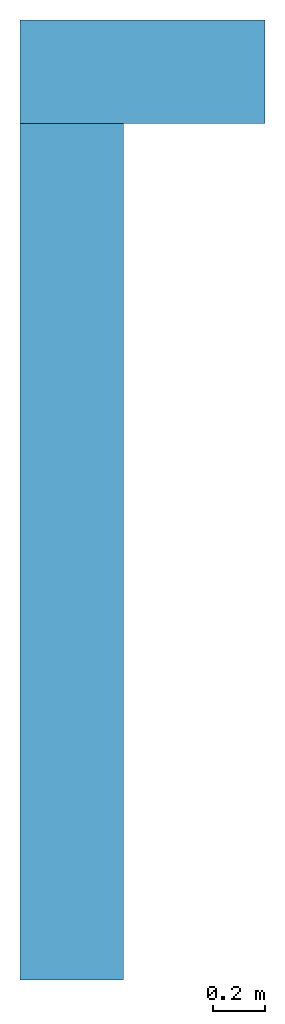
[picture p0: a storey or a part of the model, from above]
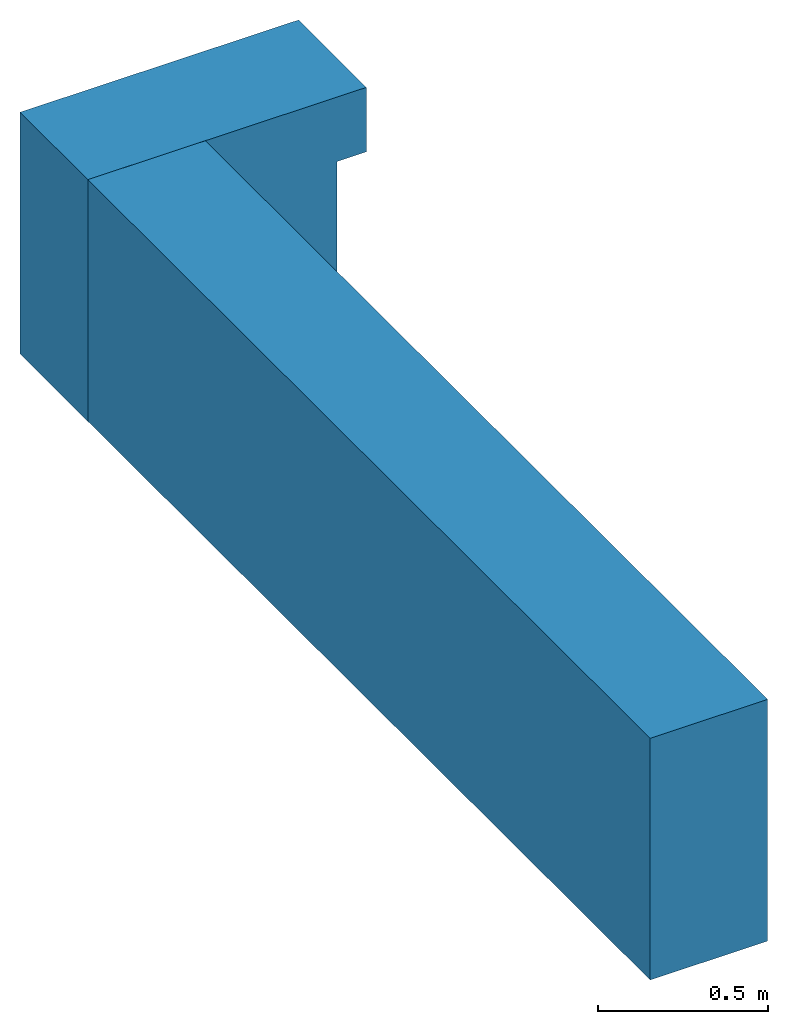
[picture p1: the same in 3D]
Properties of the parts of a building model (IFC2X3), part 3 of 3

# IfcWallStandardCase: Basic Wall:242_Værnes Innervegg 17_100mm (4)
Type - Pset_WallCommon - IsExternal: no
Type - Text - Core Kode: 100G-G M50; Vegg Kode: IV17
ePset_LocationTool - Splitting: ORIGINAL
ePset_Simplebim - Assembly Level: Leaf
Cross-Section Definition - Cross-Section: Vertical
Phasing - Phase Created: Som Bygget
Structural - Structural Usage: Non-bearing; Structural: no
Identity Data - Workset: XTA Terminal A
Other - Type: 242_Værnes Innervegg 17_100mm; Family: Basic Wall; Family and Type: Basic Wall: 242_Værnes Innervegg 17_100mm; Type Id: 7247508
Pset_ReinforcementBarPitchOfWall - Reference: 242_Værnes Innervegg 17_100mm; sets with these values: 2
ePset_SimplebimBasicQuantities - Thickness (Simplebim): 130 mm
Pset_WallCommon - Reference: 242_Værnes Innervegg 17_100mm; ExtendToStructure: no; LoadBearing: no
Constraints - Top Constraint: Up to level: M01 Hovedetasje; Base Constraint: H01 Hovedetasje; Base Extension Distance: 0 mm; Base is Attached: no; Related to Mass: no; Room Bounding: yes; Top Extension Distance: 0 mm; Top is Attached: no; Location Line: Finish Face: Interior
Name (Basic Wall:242_Værnes Innervegg 17_100mm:...) | Volume (m3) = Volume, net (Simplebim) (m3) | Length (mm) | Area (m2) = Area, side, gross, larger (Simplebim) (m2) = Area, side, net, larger (Simplebim) (m2) = Area, largest surface, net (Simplebim) (m2) | Area, side, gross, AABB (Simplebim) (m2) | Length (Simplebim) (mm) | Height (Simplebim) (mm) = Unconnected Height (mm) | Area, side, gross, smaller (Simplebim) (m2) = Area, side, net, smaller (Simplebim) (m2) | Area, side, net, average (Simplebim) (m2) = Area, side, gross, average (Simplebim) (m2) | Top Offset (mm) | Base Offset (mm)
13148432 | 1.14085 | 13451.4 | 8.77577 | 8.77584 | 13451.5 | 652.406 | 8.77577 | 8.77577 | 0 | 2600 | Identity Data - TA Workset: yes
13148434 | 1.26234 | 2675.01 | 9.71049 | 9.71049 | 2675.07 | 3630 | 9.71009 | 9.71029 | 377.594 | 0 | Identity Data - TA Workset: yes
18584985 | 0.381801 | 809.071 | 2.93693 | 2.93693 | 809.071 | 3630 | 2.93693 | 2.93693 | 377.594 | 0
18585010 | 0.171078 | 427.531 | 1.31599 | 1.31599 | 362.531 | 3630 | 1.31599 | 1.31599 | 377.594 | 0
